VERSION 5.7 ;
  NOWIREEXTENSIONATPIN ON ;
  DIVIDERCHAR "/" ;
  BUSBITCHARS "[]" ;
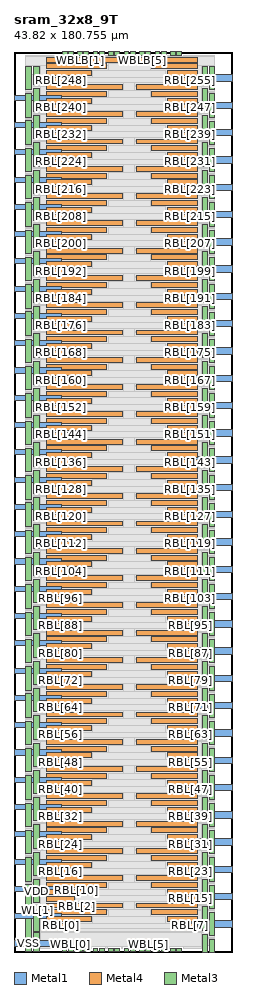
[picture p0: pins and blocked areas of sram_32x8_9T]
MACRO sram_32x8_9T
  CLASS BLOCK ;
  FOREIGN sram_32x8_9T ;
  ORIGIN -3.555 -0.080 ;
  SIZE 43.820 BY 180.755 ;
  PIN A[0]
    ANTENNADIFFAREA 2.832000 ;
    PORT
      LAYER Metal1 ;
        RECT 39.145 5.050 47.375 6.350 ;
    END
  END A[0]
  PIN A[1]
    ANTENNADIFFAREA 2.832000 ;
    PORT
      LAYER Metal1 ;
        RECT 39.145 10.530 47.375 11.830 ;
    END
  END A[1]
  PIN A[2]
    ANTENNADIFFAREA 2.832000 ;
    PORT
      LAYER Metal1 ;
        RECT 39.145 16.010 47.375 17.310 ;
    END
  END A[2]
  PIN A[3]
    ANTENNADIFFAREA 2.832000 ;
    PORT
      LAYER Metal1 ;
        RECT 39.145 21.490 47.375 22.790 ;
    END
  END A[3]
  PIN A[4]
    ANTENNADIFFAREA 2.832000 ;
    PORT
      LAYER Metal1 ;
        RECT 39.145 26.970 47.375 28.270 ;
    END
  END A[4]
  PIN A[5]
    ANTENNADIFFAREA 2.832000 ;
    PORT
      LAYER Metal1 ;
        RECT 39.145 32.450 47.375 33.750 ;
    END
  END A[5]
  PIN A[6]
    ANTENNADIFFAREA 2.832000 ;
    PORT
      LAYER Metal1 ;
        RECT 39.145 37.930 47.375 39.230 ;
    END
  END A[6]
  PIN A[7]
    ANTENNADIFFAREA 2.832000 ;
    PORT
      LAYER Metal1 ;
        RECT 39.145 43.410 47.375 44.710 ;
    END
  END A[7]
  PIN A[8]
    ANTENNADIFFAREA 2.832000 ;
    PORT
      LAYER Metal1 ;
        RECT 39.145 48.890 47.375 50.190 ;
    END
  END A[8]
  PIN A[9]
    ANTENNADIFFAREA 2.832000 ;
    PORT
      LAYER Metal1 ;
        RECT 39.145 54.370 47.375 55.670 ;
    END
  END A[9]
  PIN A[10]
    ANTENNADIFFAREA 2.832000 ;
    PORT
      LAYER Metal1 ;
        RECT 39.145 59.850 47.375 61.150 ;
    END
  END A[10]
  PIN A[11]
    ANTENNADIFFAREA 2.832000 ;
    PORT
      LAYER Metal1 ;
        RECT 39.145 65.330 47.375 66.630 ;
    END
  END A[11]
  PIN A[12]
    ANTENNADIFFAREA 2.832000 ;
    PORT
      LAYER Metal1 ;
        RECT 39.145 70.810 47.375 72.110 ;
    END
  END A[12]
  PIN A[13]
    ANTENNADIFFAREA 2.832000 ;
    PORT
      LAYER Metal1 ;
        RECT 39.145 76.290 47.375 77.590 ;
    END
  END A[13]
  PIN A[14]
    ANTENNADIFFAREA 2.832000 ;
    PORT
      LAYER Metal1 ;
        RECT 39.145 81.770 47.375 83.070 ;
    END
  END A[14]
  PIN A[15]
    ANTENNADIFFAREA 2.832000 ;
    PORT
      LAYER Metal1 ;
        RECT 39.145 87.250 47.375 88.550 ;
    END
  END A[15]
  PIN A[16]
    ANTENNADIFFAREA 2.832000 ;
    PORT
      LAYER Metal1 ;
        RECT 39.145 92.730 47.375 94.030 ;
    END
  END A[16]
  PIN A[17]
    ANTENNADIFFAREA 2.832000 ;
    PORT
      LAYER Metal1 ;
        RECT 39.145 98.210 47.375 99.510 ;
    END
  END A[17]
  PIN A[18]
    ANTENNADIFFAREA 2.832000 ;
    PORT
      LAYER Metal1 ;
        RECT 39.145 103.690 47.375 104.990 ;
    END
  END A[18]
  PIN A[19]
    ANTENNADIFFAREA 2.832000 ;
    PORT
      LAYER Metal1 ;
        RECT 39.145 109.170 47.375 110.470 ;
    END
  END A[19]
  PIN A[20]
    ANTENNADIFFAREA 2.832000 ;
    PORT
      LAYER Metal1 ;
        RECT 39.145 114.650 47.375 115.950 ;
    END
  END A[20]
  PIN A[21]
    ANTENNADIFFAREA 2.832000 ;
    PORT
      LAYER Metal1 ;
        RECT 39.145 120.130 47.375 121.430 ;
    END
  END A[21]
  PIN A[22]
    ANTENNADIFFAREA 2.832000 ;
    PORT
      LAYER Metal1 ;
        RECT 39.145 125.610 47.375 126.910 ;
    END
  END A[22]
  PIN A[23]
    ANTENNADIFFAREA 2.832000 ;
    PORT
      LAYER Metal1 ;
        RECT 39.145 131.090 47.375 132.390 ;
    END
  END A[23]
  PIN A[24]
    ANTENNADIFFAREA 2.832000 ;
    PORT
      LAYER Metal1 ;
        RECT 39.145 136.570 47.375 137.870 ;
    END
  END A[24]
  PIN A[25]
    ANTENNADIFFAREA 2.832000 ;
    PORT
      LAYER Metal1 ;
        RECT 39.145 142.050 47.375 143.350 ;
    END
  END A[25]
  PIN A[26]
    ANTENNADIFFAREA 2.832000 ;
    PORT
      LAYER Metal1 ;
        RECT 39.145 147.530 47.375 148.830 ;
    END
  END A[26]
  PIN A[27]
    ANTENNADIFFAREA 2.832000 ;
    PORT
      LAYER Metal1 ;
        RECT 39.145 153.010 47.375 154.310 ;
    END
  END A[27]
  PIN A[28]
    ANTENNADIFFAREA 2.832000 ;
    PORT
      LAYER Metal1 ;
        RECT 39.145 158.490 47.375 159.790 ;
    END
  END A[28]
  PIN A[29]
    ANTENNADIFFAREA 2.832000 ;
    PORT
      LAYER Metal1 ;
        RECT 39.145 163.970 47.375 165.270 ;
    END
  END A[29]
  PIN A[30]
    ANTENNADIFFAREA 2.832000 ;
    PORT
      LAYER Metal1 ;
        RECT 39.145 169.450 47.375 170.750 ;
    END
  END A[30]
  PIN A[31]
    ANTENNADIFFAREA 2.832000 ;
    PORT
      LAYER Metal1 ;
        RECT 39.145 174.930 47.375 176.230 ;
    END
  END A[31]
  PIN RBL[0]
    ANTENNADIFFAREA 0.511400 ;
    PORT
      LAYER Metal4 ;
        RECT 10.165 4.810 15.685 5.810 ;
    END
  END RBL[0]
  PIN RBL[1]
    ANTENNADIFFAREA 0.511400 ;
    PORT
      LAYER Metal4 ;
        RECT 10.165 6.180 19.075 7.180 ;
    END
  END RBL[1]
  PIN RBL[2]
    ANTENNADIFFAREA 0.511400 ;
    PORT
      LAYER Metal4 ;
        RECT 10.165 7.550 22.185 8.550 ;
    END
  END RBL[2]
  PIN RBL[3]
    ANTENNADIFFAREA 0.511400 ;
    PORT
      LAYER Metal4 ;
        RECT 10.165 8.920 25.295 9.920 ;
    END
  END RBL[3]
  PIN RBL[4]
    ANTENNADIFFAREA 0.511400 ;
    PORT
      LAYER Metal4 ;
        RECT 28.125 8.920 40.500 9.920 ;
    END
  END RBL[4]
  PIN RBL[5]
    ANTENNADIFFAREA 0.511400 ;
    PORT
      LAYER Metal4 ;
        RECT 31.235 7.550 40.500 8.550 ;
    END
  END RBL[5]
  PIN RBL[6]
    ANTENNADIFFAREA 0.511400 ;
    PORT
      LAYER Metal4 ;
        RECT 34.345 6.180 40.500 7.180 ;
    END
  END RBL[6]
  PIN RBL[7]
    ANTENNADIFFAREA 0.511400 ;
    PORT
      LAYER Metal4 ;
        RECT 37.455 4.810 40.500 5.810 ;
    END
  END RBL[7]
  PIN RBL[8]
    ANTENNADIFFAREA 0.511400 ;
    PORT
      LAYER Metal4 ;
        RECT 10.165 10.290 15.685 11.290 ;
    END
  END RBL[8]
  PIN RBL[9]
    ANTENNADIFFAREA 0.511400 ;
    PORT
      LAYER Metal4 ;
        RECT 10.165 11.660 19.075 12.660 ;
    END
  END RBL[9]
  PIN RBL[10]
    ANTENNADIFFAREA 0.511400 ;
    PORT
      LAYER Metal4 ;
        RECT 10.165 13.030 22.185 14.030 ;
    END
  END RBL[10]
  PIN RBL[11]
    ANTENNADIFFAREA 0.511400 ;
    PORT
      LAYER Metal4 ;
        RECT 10.165 14.400 25.295 15.400 ;
    END
  END RBL[11]
  PIN RBL[12]
    ANTENNADIFFAREA 0.511400 ;
    PORT
      LAYER Metal4 ;
        RECT 28.125 14.400 40.500 15.400 ;
    END
  END RBL[12]
  PIN RBL[13]
    ANTENNADIFFAREA 0.511400 ;
    PORT
      LAYER Metal4 ;
        RECT 31.235 13.030 40.500 14.030 ;
    END
  END RBL[13]
  PIN RBL[14]
    ANTENNADIFFAREA 0.511400 ;
    PORT
      LAYER Metal4 ;
        RECT 34.345 11.660 40.500 12.660 ;
    END
  END RBL[14]
  PIN RBL[15]
    ANTENNADIFFAREA 0.511400 ;
    PORT
      LAYER Metal4 ;
        RECT 37.455 10.290 40.500 11.290 ;
    END
  END RBL[15]
  PIN RBL[16]
    ANTENNADIFFAREA 0.511400 ;
    PORT
      LAYER Metal4 ;
        RECT 10.165 15.770 15.685 16.770 ;
    END
  END RBL[16]
  PIN RBL[17]
    ANTENNADIFFAREA 0.511400 ;
    PORT
      LAYER Metal4 ;
        RECT 10.165 17.140 19.075 18.140 ;
    END
  END RBL[17]
  PIN RBL[18]
    ANTENNADIFFAREA 0.511400 ;
    PORT
      LAYER Metal4 ;
        RECT 10.165 18.510 22.185 19.510 ;
    END
  END RBL[18]
  PIN RBL[19]
    ANTENNADIFFAREA 0.511400 ;
    PORT
      LAYER Metal4 ;
        RECT 10.165 19.880 25.295 20.880 ;
    END
  END RBL[19]
  PIN RBL[20]
    ANTENNADIFFAREA 0.511400 ;
    PORT
      LAYER Metal4 ;
        RECT 28.125 19.880 40.500 20.880 ;
    END
  END RBL[20]
  PIN RBL[21]
    ANTENNADIFFAREA 0.511400 ;
    PORT
      LAYER Metal4 ;
        RECT 31.235 18.510 40.500 19.510 ;
    END
  END RBL[21]
  PIN RBL[22]
    ANTENNADIFFAREA 0.511400 ;
    PORT
      LAYER Metal4 ;
        RECT 34.345 17.140 40.500 18.140 ;
    END
  END RBL[22]
  PIN RBL[23]
    ANTENNADIFFAREA 0.511400 ;
    PORT
      LAYER Metal4 ;
        RECT 37.455 15.770 40.500 16.770 ;
    END
  END RBL[23]
  PIN RBL[24]
    ANTENNADIFFAREA 0.511400 ;
    PORT
      LAYER Metal4 ;
        RECT 10.165 21.250 15.685 22.250 ;
    END
  END RBL[24]
  PIN RBL[25]
    ANTENNADIFFAREA 0.511400 ;
    PORT
      LAYER Metal4 ;
        RECT 10.165 22.620 19.075 23.620 ;
    END
  END RBL[25]
  PIN RBL[26]
    ANTENNADIFFAREA 0.511400 ;
    PORT
      LAYER Metal4 ;
        RECT 10.165 23.990 22.185 24.990 ;
    END
  END RBL[26]
  PIN RBL[27]
    ANTENNADIFFAREA 0.511400 ;
    PORT
      LAYER Metal4 ;
        RECT 10.165 25.360 25.295 26.360 ;
    END
  END RBL[27]
  PIN RBL[28]
    ANTENNADIFFAREA 0.511400 ;
    PORT
      LAYER Metal4 ;
        RECT 28.125 25.360 40.500 26.360 ;
    END
  END RBL[28]
  PIN RBL[29]
    ANTENNADIFFAREA 0.511400 ;
    PORT
      LAYER Metal4 ;
        RECT 31.235 23.990 40.500 24.990 ;
    END
  END RBL[29]
  PIN RBL[30]
    ANTENNADIFFAREA 0.511400 ;
    PORT
      LAYER Metal4 ;
        RECT 34.345 22.620 40.500 23.620 ;
    END
  END RBL[30]
  PIN RBL[31]
    ANTENNADIFFAREA 0.511400 ;
    PORT
      LAYER Metal4 ;
        RECT 37.455 21.250 40.500 22.250 ;
    END
  END RBL[31]
  PIN RBL[32]
    ANTENNADIFFAREA 0.511400 ;
    PORT
      LAYER Metal4 ;
        RECT 10.165 26.730 15.685 27.730 ;
    END
  END RBL[32]
  PIN RBL[33]
    ANTENNADIFFAREA 0.511400 ;
    PORT
      LAYER Metal4 ;
        RECT 10.165 28.100 19.075 29.100 ;
    END
  END RBL[33]
  PIN RBL[34]
    ANTENNADIFFAREA 0.511400 ;
    PORT
      LAYER Metal4 ;
        RECT 10.165 29.470 22.185 30.470 ;
    END
  END RBL[34]
  PIN RBL[35]
    ANTENNADIFFAREA 0.511400 ;
    PORT
      LAYER Metal4 ;
        RECT 10.165 30.840 25.295 31.840 ;
    END
  END RBL[35]
  PIN RBL[36]
    ANTENNADIFFAREA 0.511400 ;
    PORT
      LAYER Metal4 ;
        RECT 28.125 30.840 40.500 31.840 ;
    END
  END RBL[36]
  PIN RBL[37]
    ANTENNADIFFAREA 0.511400 ;
    PORT
      LAYER Metal4 ;
        RECT 31.235 29.470 40.500 30.470 ;
    END
  END RBL[37]
  PIN RBL[38]
    ANTENNADIFFAREA 0.511400 ;
    PORT
      LAYER Metal4 ;
        RECT 34.345 28.100 40.500 29.100 ;
    END
  END RBL[38]
  PIN RBL[39]
    ANTENNADIFFAREA 0.511400 ;
    PORT
      LAYER Metal4 ;
        RECT 37.455 26.730 40.500 27.730 ;
    END
  END RBL[39]
  PIN RBL[40]
    ANTENNADIFFAREA 0.511400 ;
    PORT
      LAYER Metal4 ;
        RECT 10.165 32.210 15.685 33.210 ;
    END
  END RBL[40]
  PIN RBL[41]
    ANTENNADIFFAREA 0.511400 ;
    PORT
      LAYER Metal4 ;
        RECT 10.165 33.580 19.075 34.580 ;
    END
  END RBL[41]
  PIN RBL[42]
    ANTENNADIFFAREA 0.511400 ;
    PORT
      LAYER Metal4 ;
        RECT 10.165 34.950 22.185 35.950 ;
    END
  END RBL[42]
  PIN RBL[43]
    ANTENNADIFFAREA 0.511400 ;
    PORT
      LAYER Metal4 ;
        RECT 10.165 36.320 25.295 37.320 ;
    END
  END RBL[43]
  PIN RBL[44]
    ANTENNADIFFAREA 0.511400 ;
    PORT
      LAYER Metal4 ;
        RECT 28.125 36.320 40.500 37.320 ;
    END
  END RBL[44]
  PIN RBL[45]
    ANTENNADIFFAREA 0.511400 ;
    PORT
      LAYER Metal4 ;
        RECT 31.235 34.950 40.500 35.950 ;
    END
  END RBL[45]
  PIN RBL[46]
    ANTENNADIFFAREA 0.511400 ;
    PORT
      LAYER Metal4 ;
        RECT 34.345 33.580 40.500 34.580 ;
    END
  END RBL[46]
  PIN RBL[47]
    ANTENNADIFFAREA 0.511400 ;
    PORT
      LAYER Metal4 ;
        RECT 37.455 32.210 40.500 33.210 ;
    END
  END RBL[47]
  PIN RBL[48]
    ANTENNADIFFAREA 0.511400 ;
    PORT
      LAYER Metal4 ;
        RECT 10.165 37.690 15.685 38.690 ;
    END
  END RBL[48]
  PIN RBL[49]
    ANTENNADIFFAREA 0.511400 ;
    PORT
      LAYER Metal4 ;
        RECT 10.165 39.060 19.075 40.060 ;
    END
  END RBL[49]
  PIN RBL[50]
    ANTENNADIFFAREA 0.511400 ;
    PORT
      LAYER Metal4 ;
        RECT 10.165 40.430 22.185 41.430 ;
    END
  END RBL[50]
  PIN RBL[51]
    ANTENNADIFFAREA 0.511400 ;
    PORT
      LAYER Metal4 ;
        RECT 10.165 41.800 25.295 42.800 ;
    END
  END RBL[51]
  PIN RBL[52]
    ANTENNADIFFAREA 0.511400 ;
    PORT
      LAYER Metal4 ;
        RECT 28.125 41.800 40.500 42.800 ;
    END
  END RBL[52]
  PIN RBL[53]
    ANTENNADIFFAREA 0.511400 ;
    PORT
      LAYER Metal4 ;
        RECT 31.235 40.430 40.500 41.430 ;
    END
  END RBL[53]
  PIN RBL[54]
    ANTENNADIFFAREA 0.511400 ;
    PORT
      LAYER Metal4 ;
        RECT 34.345 39.060 40.500 40.060 ;
    END
  END RBL[54]
  PIN RBL[55]
    ANTENNADIFFAREA 0.511400 ;
    PORT
      LAYER Metal4 ;
        RECT 37.455 37.690 40.500 38.690 ;
    END
  END RBL[55]
  PIN RBL[56]
    ANTENNADIFFAREA 0.511400 ;
    PORT
      LAYER Metal4 ;
        RECT 10.165 43.170 15.685 44.170 ;
    END
  END RBL[56]
  PIN RBL[57]
    ANTENNADIFFAREA 0.511400 ;
    PORT
      LAYER Metal4 ;
        RECT 10.165 44.540 19.075 45.540 ;
    END
  END RBL[57]
  PIN RBL[58]
    ANTENNADIFFAREA 0.511400 ;
    PORT
      LAYER Metal4 ;
        RECT 10.165 45.910 22.185 46.910 ;
    END
  END RBL[58]
  PIN RBL[59]
    ANTENNADIFFAREA 0.511400 ;
    PORT
      LAYER Metal4 ;
        RECT 10.165 47.280 25.295 48.280 ;
    END
  END RBL[59]
  PIN RBL[60]
    ANTENNADIFFAREA 0.511400 ;
    PORT
      LAYER Metal4 ;
        RECT 28.125 47.280 40.500 48.280 ;
    END
  END RBL[60]
  PIN RBL[61]
    ANTENNADIFFAREA 0.511400 ;
    PORT
      LAYER Metal4 ;
        RECT 31.235 45.910 40.500 46.910 ;
    END
  END RBL[61]
  PIN RBL[62]
    ANTENNADIFFAREA 0.511400 ;
    PORT
      LAYER Metal4 ;
        RECT 34.345 44.540 40.500 45.540 ;
    END
  END RBL[62]
  PIN RBL[63]
    ANTENNADIFFAREA 0.511400 ;
    PORT
      LAYER Metal4 ;
        RECT 37.455 43.170 40.500 44.170 ;
    END
  END RBL[63]
  PIN RBL[64]
    ANTENNADIFFAREA 0.511400 ;
    PORT
      LAYER Metal4 ;
        RECT 10.165 48.650 15.685 49.650 ;
    END
  END RBL[64]
  PIN RBL[65]
    ANTENNADIFFAREA 0.511400 ;
    PORT
      LAYER Metal4 ;
        RECT 10.165 50.020 19.075 51.020 ;
    END
  END RBL[65]
  PIN RBL[66]
    ANTENNADIFFAREA 0.511400 ;
    PORT
      LAYER Metal4 ;
        RECT 10.165 51.390 22.185 52.390 ;
    END
  END RBL[66]
  PIN RBL[67]
    ANTENNADIFFAREA 0.511400 ;
    PORT
      LAYER Metal4 ;
        RECT 10.165 52.760 25.295 53.760 ;
    END
  END RBL[67]
  PIN RBL[68]
    ANTENNADIFFAREA 0.511400 ;
    PORT
      LAYER Metal4 ;
        RECT 28.125 52.760 40.500 53.760 ;
    END
  END RBL[68]
  PIN RBL[69]
    ANTENNADIFFAREA 0.511400 ;
    PORT
      LAYER Metal4 ;
        RECT 31.235 51.390 40.500 52.390 ;
    END
  END RBL[69]
  PIN RBL[70]
    ANTENNADIFFAREA 0.511400 ;
    PORT
      LAYER Metal4 ;
        RECT 34.345 50.020 40.500 51.020 ;
    END
  END RBL[70]
  PIN RBL[71]
    ANTENNADIFFAREA 0.511400 ;
    PORT
      LAYER Metal4 ;
        RECT 37.455 48.650 40.500 49.650 ;
    END
  END RBL[71]
  PIN RBL[72]
    ANTENNADIFFAREA 0.511400 ;
    PORT
      LAYER Metal4 ;
        RECT 10.165 54.130 15.685 55.130 ;
    END
  END RBL[72]
  PIN RBL[73]
    ANTENNADIFFAREA 0.511400 ;
    PORT
      LAYER Metal4 ;
        RECT 10.165 55.500 19.075 56.500 ;
    END
  END RBL[73]
  PIN RBL[74]
    ANTENNADIFFAREA 0.511400 ;
    PORT
      LAYER Metal4 ;
        RECT 10.165 56.870 22.185 57.870 ;
    END
  END RBL[74]
  PIN RBL[75]
    ANTENNADIFFAREA 0.511400 ;
    PORT
      LAYER Metal4 ;
        RECT 10.165 58.240 25.295 59.240 ;
    END
  END RBL[75]
  PIN RBL[76]
    ANTENNADIFFAREA 0.511400 ;
    PORT
      LAYER Metal4 ;
        RECT 28.125 58.240 40.500 59.240 ;
    END
  END RBL[76]
  PIN RBL[77]
    ANTENNADIFFAREA 0.511400 ;
    PORT
      LAYER Metal4 ;
        RECT 31.235 56.870 40.500 57.870 ;
    END
  END RBL[77]
  PIN RBL[78]
    ANTENNADIFFAREA 0.511400 ;
    PORT
      LAYER Metal4 ;
        RECT 34.345 55.500 40.500 56.500 ;
    END
  END RBL[78]
  PIN RBL[79]
    ANTENNADIFFAREA 0.511400 ;
    PORT
      LAYER Metal4 ;
        RECT 37.455 54.130 40.500 55.130 ;
    END
  END RBL[79]
  PIN RBL[80]
    ANTENNADIFFAREA 0.511400 ;
    PORT
      LAYER Metal4 ;
        RECT 10.165 59.610 15.685 60.610 ;
    END
  END RBL[80]
  PIN RBL[81]
    ANTENNADIFFAREA 0.511400 ;
    PORT
      LAYER Metal4 ;
        RECT 10.165 60.980 19.075 61.980 ;
    END
  END RBL[81]
  PIN RBL[82]
    ANTENNADIFFAREA 0.511400 ;
    PORT
      LAYER Metal4 ;
        RECT 10.165 62.350 22.185 63.350 ;
    END
  END RBL[82]
  PIN RBL[83]
    ANTENNADIFFAREA 0.511400 ;
    PORT
      LAYER Metal4 ;
        RECT 10.165 63.720 25.295 64.720 ;
    END
  END RBL[83]
  PIN RBL[84]
    ANTENNADIFFAREA 0.511400 ;
    PORT
      LAYER Metal4 ;
        RECT 28.125 63.720 40.500 64.720 ;
    END
  END RBL[84]
  PIN RBL[85]
    ANTENNADIFFAREA 0.511400 ;
    PORT
      LAYER Metal4 ;
        RECT 31.235 62.350 40.500 63.350 ;
    END
  END RBL[85]
  PIN RBL[86]
    ANTENNADIFFAREA 0.511400 ;
    PORT
      LAYER Metal4 ;
        RECT 34.345 60.980 40.500 61.980 ;
    END
  END RBL[86]
  PIN RBL[87]
    ANTENNADIFFAREA 0.511400 ;
    PORT
      LAYER Metal4 ;
        RECT 37.455 59.610 40.500 60.610 ;
    END
  END RBL[87]
  PIN RBL[88]
    ANTENNADIFFAREA 0.511400 ;
    PORT
      LAYER Metal4 ;
        RECT 10.165 65.090 15.685 66.090 ;
    END
  END RBL[88]
  PIN RBL[89]
    ANTENNADIFFAREA 0.511400 ;
    PORT
      LAYER Metal4 ;
        RECT 10.165 66.460 19.075 67.460 ;
    END
  END RBL[89]
  PIN RBL[90]
    ANTENNADIFFAREA 0.511400 ;
    PORT
      LAYER Metal4 ;
        RECT 10.165 67.830 22.185 68.830 ;
    END
  END RBL[90]
  PIN RBL[91]
    ANTENNADIFFAREA 0.511400 ;
    PORT
      LAYER Metal4 ;
        RECT 10.165 69.200 25.295 70.200 ;
    END
  END RBL[91]
  PIN RBL[92]
    ANTENNADIFFAREA 0.511400 ;
    PORT
      LAYER Metal4 ;
        RECT 28.125 69.200 40.500 70.200 ;
    END
  END RBL[92]
  PIN RBL[93]
    ANTENNADIFFAREA 0.511400 ;
    PORT
      LAYER Metal4 ;
        RECT 31.235 67.830 40.500 68.830 ;
    END
  END RBL[93]
  PIN RBL[94]
    ANTENNADIFFAREA 0.511400 ;
    PORT
      LAYER Metal4 ;
        RECT 34.345 66.460 40.500 67.460 ;
    END
  END RBL[94]
  PIN RBL[95]
    ANTENNADIFFAREA 0.511400 ;
    PORT
      LAYER Metal4 ;
        RECT 37.455 65.090 40.500 66.090 ;
    END
  END RBL[95]
  PIN RBL[96]
    ANTENNADIFFAREA 0.511400 ;
    PORT
      LAYER Metal4 ;
        RECT 10.165 70.570 15.685 71.570 ;
    END
  END RBL[96]
  PIN RBL[97]
    ANTENNADIFFAREA 0.511400 ;
    PORT
      LAYER Metal4 ;
        RECT 10.165 71.940 19.075 72.940 ;
    END
  END RBL[97]
  PIN RBL[98]
    ANTENNADIFFAREA 0.511400 ;
    PORT
      LAYER Metal4 ;
        RECT 10.165 73.310 22.185 74.310 ;
    END
  END RBL[98]
  PIN RBL[99]
    ANTENNADIFFAREA 0.511400 ;
    PORT
      LAYER Metal4 ;
        RECT 10.165 74.680 25.295 75.680 ;
    END
  END RBL[99]
  PIN RBL[100]
    ANTENNADIFFAREA 0.511400 ;
    PORT
      LAYER Metal4 ;
        RECT 28.125 74.680 40.500 75.680 ;
    END
  END RBL[100]
  PIN RBL[101]
    ANTENNADIFFAREA 0.511400 ;
    PORT
      LAYER Metal4 ;
        RECT 31.235 73.310 40.500 74.310 ;
    END
  END RBL[101]
  PIN RBL[102]
    ANTENNADIFFAREA 0.511400 ;
    PORT
      LAYER Metal4 ;
        RECT 34.345 71.940 40.500 72.940 ;
    END
  END RBL[102]
  PIN RBL[103]
    ANTENNADIFFAREA 0.511400 ;
    PORT
      LAYER Metal4 ;
        RECT 37.455 70.570 40.500 71.570 ;
    END
  END RBL[103]
  PIN RBL[104]
    ANTENNADIFFAREA 0.511400 ;
    PORT
      LAYER Metal4 ;
        RECT 10.165 76.050 15.685 77.050 ;
    END
  END RBL[104]
  PIN RBL[105]
    ANTENNADIFFAREA 0.511400 ;
    PORT
      LAYER Metal4 ;
        RECT 10.165 77.420 19.075 78.420 ;
    END
  END RBL[105]
  PIN RBL[106]
    ANTENNADIFFAREA 0.511400 ;
    PORT
      LAYER Metal4 ;
        RECT 10.165 78.790 22.185 79.790 ;
    END
  END RBL[106]
  PIN RBL[107]
    ANTENNADIFFAREA 0.511400 ;
    PORT
      LAYER Metal4 ;
        RECT 10.165 80.160 25.295 81.160 ;
    END
  END RBL[107]
  PIN RBL[108]
    ANTENNADIFFAREA 0.511400 ;
    PORT
      LAYER Metal4 ;
        RECT 28.125 80.160 40.500 81.160 ;
    END
  END RBL[108]
  PIN RBL[109]
    ANTENNADIFFAREA 0.511400 ;
    PORT
      LAYER Metal4 ;
        RECT 31.235 78.790 40.500 79.790 ;
    END
  END RBL[109]
  PIN RBL[110]
    ANTENNADIFFAREA 0.511400 ;
    PORT
      LAYER Metal4 ;
        RECT 34.345 77.420 40.500 78.420 ;
    END
  END RBL[110]
  PIN RBL[111]
    ANTENNADIFFAREA 0.511400 ;
    PORT
      LAYER Metal4 ;
        RECT 37.455 76.050 40.500 77.050 ;
    END
  END RBL[111]
  PIN RBL[112]
    ANTENNADIFFAREA 0.511400 ;
    PORT
      LAYER Metal4 ;
        RECT 10.165 81.530 15.685 82.530 ;
    END
  END RBL[112]
  PIN RBL[113]
    ANTENNADIFFAREA 0.511400 ;
    PORT
      LAYER Metal4 ;
        RECT 10.165 82.900 19.075 83.900 ;
    END
  END RBL[113]
  PIN RBL[114]
    ANTENNADIFFAREA 0.511400 ;
    PORT
      LAYER Metal4 ;
        RECT 10.165 84.270 22.185 85.270 ;
    END
  END RBL[114]
  PIN RBL[115]
    ANTENNADIFFAREA 0.511400 ;
    PORT
      LAYER Metal4 ;
        RECT 10.165 85.640 25.295 86.640 ;
    END
  END RBL[115]
  PIN RBL[116]
    ANTENNADIFFAREA 0.511400 ;
    PORT
      LAYER Metal4 ;
        RECT 28.125 85.640 40.500 86.640 ;
    END
  END RBL[116]
  PIN RBL[117]
    ANTENNADIFFAREA 0.511400 ;
    PORT
      LAYER Metal4 ;
        RECT 31.235 84.270 40.500 85.270 ;
    END
  END RBL[117]
  PIN RBL[118]
    ANTENNADIFFAREA 0.511400 ;
    PORT
      LAYER Metal4 ;
        RECT 34.345 82.900 40.500 83.900 ;
    END
  END RBL[118]
  PIN RBL[119]
    ANTENNADIFFAREA 0.511400 ;
    PORT
      LAYER Metal4 ;
        RECT 37.455 81.530 40.500 82.530 ;
    END
  END RBL[119]
  PIN RBL[120]
    ANTENNADIFFAREA 0.511400 ;
    PORT
      LAYER Metal4 ;
        RECT 10.165 87.010 15.685 88.010 ;
    END
  END RBL[120]
  PIN RBL[121]
    ANTENNADIFFAREA 0.511400 ;
    PORT
      LAYER Metal4 ;
        RECT 10.165 88.380 19.075 89.380 ;
    END
  END RBL[121]
  PIN RBL[122]
    ANTENNADIFFAREA 0.511400 ;
    PORT
      LAYER Metal4 ;
        RECT 10.165 89.750 22.185 90.750 ;
    END
  END RBL[122]
  PIN RBL[123]
    ANTENNADIFFAREA 0.511400 ;
    PORT
      LAYER Metal4 ;
        RECT 10.165 91.120 25.295 92.120 ;
    END
  END RBL[123]
  PIN RBL[124]
    ANTENNADIFFAREA 0.511400 ;
    PORT
      LAYER Metal4 ;
        RECT 28.125 91.120 40.500 92.120 ;
    END
  END RBL[124]
  PIN RBL[125]
    ANTENNADIFFAREA 0.511400 ;
    PORT
      LAYER Metal4 ;
        RECT 31.235 89.750 40.500 90.750 ;
    END
  END RBL[125]
  PIN RBL[126]
    ANTENNADIFFAREA 0.511400 ;
    PORT
      LAYER Metal4 ;
        RECT 34.345 88.380 40.500 89.380 ;
    END
  END RBL[126]
  PIN RBL[127]
    ANTENNADIFFAREA 0.511400 ;
    PORT
      LAYER Metal4 ;
        RECT 37.455 87.010 40.500 88.010 ;
    END
  END RBL[127]
  PIN RBL[128]
    ANTENNADIFFAREA 0.511400 ;
    PORT
      LAYER Metal4 ;
        RECT 10.165 92.490 15.685 93.490 ;
    END
  END RBL[128]
  PIN RBL[129]
    ANTENNADIFFAREA 0.511400 ;
    PORT
      LAYER Metal4 ;
        RECT 10.165 93.860 19.075 94.860 ;
    END
  END RBL[129]
  PIN RBL[130]
    ANTENNADIFFAREA 0.511400 ;
    PORT
      LAYER Metal4 ;
        RECT 10.165 95.230 22.185 96.230 ;
    END
  END RBL[130]
  PIN RBL[131]
    ANTENNADIFFAREA 0.511400 ;
    PORT
      LAYER Metal4 ;
        RECT 10.165 96.600 25.295 97.600 ;
    END
  END RBL[131]
  PIN RBL[132]
    ANTENNADIFFAREA 0.511400 ;
    PORT
      LAYER Metal4 ;
        RECT 28.125 96.600 40.500 97.600 ;
    END
  END RBL[132]
  PIN RBL[133]
    ANTENNADIFFAREA 0.511400 ;
    PORT
      LAYER Metal4 ;
        RECT 31.235 95.230 40.500 96.230 ;
    END
  END RBL[133]
  PIN RBL[134]
    ANTENNADIFFAREA 0.511400 ;
    PORT
      LAYER Metal4 ;
        RECT 34.345 93.860 40.500 94.860 ;
    END
  END RBL[134]
  PIN RBL[135]
    ANTENNADIFFAREA 0.511400 ;
    PORT
      LAYER Metal4 ;
        RECT 37.455 92.490 40.500 93.490 ;
    END
  END RBL[135]
  PIN RBL[136]
    ANTENNADIFFAREA 0.511400 ;
    PORT
      LAYER Metal4 ;
        RECT 10.165 97.970 15.685 98.970 ;
    END
  END RBL[136]
  PIN RBL[137]
    ANTENNADIFFAREA 0.511400 ;
    PORT
      LAYER Metal4 ;
        RECT 10.165 99.340 19.075 100.340 ;
    END
  END RBL[137]
  PIN RBL[138]
    ANTENNADIFFAREA 0.511400 ;
    PORT
      LAYER Metal4 ;
        RECT 10.165 100.710 22.185 101.710 ;
    END
  END RBL[138]
  PIN RBL[139]
    ANTENNADIFFAREA 0.511400 ;
    PORT
      LAYER Metal4 ;
        RECT 10.165 102.080 25.295 103.080 ;
    END
  END RBL[139]
  PIN RBL[140]
    ANTENNADIFFAREA 0.511400 ;
    PORT
      LAYER Metal4 ;
        RECT 28.125 102.080 40.500 103.080 ;
    END
  END RBL[140]
  PIN RBL[141]
    ANTENNADIFFAREA 0.511400 ;
    PORT
      LAYER Metal4 ;
        RECT 31.235 100.710 40.500 101.710 ;
    END
  END RBL[141]
  PIN RBL[142]
    ANTENNADIFFAREA 0.511400 ;
    PORT
      LAYER Metal4 ;
        RECT 34.345 99.340 40.500 100.340 ;
    END
  END RBL[142]
  PIN RBL[143]
    ANTENNADIFFAREA 0.511400 ;
    PORT
      LAYER Metal4 ;
        RECT 37.455 97.970 40.500 98.970 ;
    END
  END RBL[143]
  PIN RBL[144]
    ANTENNADIFFAREA 0.511400 ;
    PORT
      LAYER Metal4 ;
        RECT 10.165 103.450 15.685 104.450 ;
    END
  END RBL[144]
  PIN RBL[145]
    ANTENNADIFFAREA 0.511400 ;
    PORT
      LAYER Metal4 ;
        RECT 10.165 104.820 19.075 105.820 ;
    END
  END RBL[145]
  PIN RBL[146]
    ANTENNADIFFAREA 0.511400 ;
    PORT
      LAYER Metal4 ;
        RECT 10.165 106.190 22.185 107.190 ;
    END
  END RBL[146]
  PIN RBL[147]
    ANTENNADIFFAREA 0.511400 ;
    PORT
      LAYER Metal4 ;
        RECT 10.165 107.560 25.295 108.560 ;
    END
  END RBL[147]
  PIN RBL[148]
    ANTENNADIFFAREA 0.511400 ;
    PORT
      LAYER Metal4 ;
        RECT 28.125 107.560 40.500 108.560 ;
    END
  END RBL[148]
  PIN RBL[149]
    ANTENNADIFFAREA 0.511400 ;
    PORT
      LAYER Metal4 ;
        RECT 31.235 106.190 40.500 107.190 ;
    END
  END RBL[149]
  PIN RBL[150]
    ANTENNADIFFAREA 0.511400 ;
    PORT
      LAYER Metal4 ;
        RECT 34.345 104.820 40.500 105.820 ;
    END
  END RBL[150]
  PIN RBL[151]
    ANTENNADIFFAREA 0.511400 ;
    PORT
      LAYER Metal4 ;
        RECT 37.455 103.450 40.500 104.450 ;
    END
  END RBL[151]
  PIN RBL[152]
    ANTENNADIFFAREA 0.511400 ;
    PORT
      LAYER Metal4 ;
        RECT 10.165 108.930 15.685 109.930 ;
    END
  END RBL[152]
  PIN RBL[153]
    ANTENNADIFFAREA 0.511400 ;
    PORT
      LAYER Metal4 ;
        RECT 10.165 110.300 19.075 111.300 ;
    END
  END RBL[153]
  PIN RBL[154]
    ANTENNADIFFAREA 0.511400 ;
    PORT
      LAYER Metal4 ;
        RECT 10.165 111.670 22.185 112.670 ;
    END
  END RBL[154]
  PIN RBL[155]
    ANTENNADIFFAREA 0.511400 ;
    PORT
      LAYER Metal4 ;
        RECT 10.165 113.040 25.295 114.040 ;
    END
  END RBL[155]
  PIN RBL[156]
    ANTENNADIFFAREA 0.511400 ;
    PORT
      LAYER Metal4 ;
        RECT 28.125 113.040 40.500 114.040 ;
    END
  END RBL[156]
  PIN RBL[157]
    ANTENNADIFFAREA 0.511400 ;
    PORT
      LAYER Metal4 ;
        RECT 31.235 111.670 40.500 112.670 ;
    END
  END RBL[157]
  PIN RBL[158]
    ANTENNADIFFAREA 0.511400 ;
    PORT
      LAYER Metal4 ;
        RECT 34.345 110.300 40.500 111.300 ;
    END
  END RBL[158]
  PIN RBL[159]
    ANTENNADIFFAREA 0.511400 ;
    PORT
      LAYER Metal4 ;
        RECT 37.455 108.930 40.500 109.930 ;
    END
  END RBL[159]
  PIN RBL[160]
    ANTENNADIFFAREA 0.511400 ;
    PORT
      LAYER Metal4 ;
        RECT 10.165 114.410 15.685 115.410 ;
    END
  END RBL[160]
  PIN RBL[161]
    ANTENNADIFFAREA 0.511400 ;
    PORT
      LAYER Metal4 ;
        RECT 10.165 115.780 19.075 116.780 ;
    END
  END RBL[161]
  PIN RBL[162]
    ANTENNADIFFAREA 0.511400 ;
    PORT
      LAYER Metal4 ;
        RECT 10.165 117.150 22.185 118.150 ;
    END
  END RBL[162]
  PIN RBL[163]
    ANTENNADIFFAREA 0.511400 ;
    PORT
      LAYER Metal4 ;
        RECT 10.165 118.520 25.295 119.520 ;
    END
  END RBL[163]
  PIN RBL[164]
    ANTENNADIFFAREA 0.511400 ;
    PORT
      LAYER Metal4 ;
        RECT 28.125 118.520 40.500 119.520 ;
    END
  END RBL[164]
  PIN RBL[165]
    ANTENNADIFFAREA 0.511400 ;
    PORT
      LAYER Metal4 ;
        RECT 31.235 117.150 40.500 118.150 ;
    END
  END RBL[165]
  PIN RBL[166]
    ANTENNADIFFAREA 0.511400 ;
    PORT
      LAYER Metal4 ;
        RECT 34.345 115.780 40.500 116.780 ;
    END
  END RBL[166]
  PIN RBL[167]
    ANTENNADIFFAREA 0.511400 ;
    PORT
      LAYER Metal4 ;
        RECT 37.455 114.410 40.500 115.410 ;
    END
  END RBL[167]
  PIN RBL[168]
    ANTENNADIFFAREA 0.511400 ;
    PORT
      LAYER Metal4 ;
        RECT 10.165 119.890 15.685 120.890 ;
    END
  END RBL[168]
  PIN RBL[169]
    ANTENNADIFFAREA 0.511400 ;
    PORT
      LAYER Metal4 ;
        RECT 10.165 121.260 19.075 122.260 ;
    END
  END RBL[169]
  PIN RBL[170]
    ANTENNADIFFAREA 0.511400 ;
    PORT
      LAYER Metal4 ;
        RECT 10.165 122.630 22.185 123.630 ;
    END
  END RBL[170]
  PIN RBL[171]
    ANTENNADIFFAREA 0.511400 ;
    PORT
      LAYER Metal4 ;
        RECT 10.165 124.000 25.295 125.000 ;
    END
  END RBL[171]
  PIN RBL[172]
    ANTENNADIFFAREA 0.511400 ;
    PORT
      LAYER Metal4 ;
        RECT 28.125 124.000 40.500 125.000 ;
    END
  END RBL[172]
  PIN RBL[173]
    ANTENNADIFFAREA 0.511400 ;
    PORT
      LAYER Metal4 ;
        RECT 31.235 122.630 40.500 123.630 ;
    END
  END RBL[173]
  PIN RBL[174]
    ANTENNADIFFAREA 0.511400 ;
    PORT
      LAYER Metal4 ;
        RECT 34.345 121.260 40.500 122.260 ;
    END
  END RBL[174]
  PIN RBL[175]
    ANTENNADIFFAREA 0.511400 ;
    PORT
      LAYER Metal4 ;
        RECT 37.455 119.890 40.500 120.890 ;
    END
  END RBL[175]
  PIN RBL[176]
    ANTENNADIFFAREA 0.511400 ;
    PORT
      LAYER Metal4 ;
        RECT 10.165 125.370 15.685 126.370 ;
    END
  END RBL[176]
  PIN RBL[177]
    ANTENNADIFFAREA 0.511400 ;
    PORT
      LAYER Metal4 ;
        RECT 10.165 126.740 19.075 127.740 ;
    END
  END RBL[177]
  PIN RBL[178]
    ANTENNADIFFAREA 0.511400 ;
    PORT
      LAYER Metal4 ;
        RECT 10.165 128.110 22.185 129.110 ;
    END
  END RBL[178]
  PIN RBL[179]
    ANTENNADIFFAREA 0.511400 ;
    PORT
      LAYER Metal4 ;
        RECT 10.165 129.480 25.295 130.480 ;
    END
  END RBL[179]
  PIN RBL[180]
    ANTENNADIFFAREA 0.511400 ;
    PORT
      LAYER Metal4 ;
        RECT 28.125 129.480 40.500 130.480 ;
    END
  END RBL[180]
  PIN RBL[181]
    ANTENNADIFFAREA 0.511400 ;
    PORT
      LAYER Metal4 ;
        RECT 31.235 128.110 40.500 129.110 ;
    END
  END RBL[181]
  PIN RBL[182]
    ANTENNADIFFAREA 0.511400 ;
    PORT
      LAYER Metal4 ;
        RECT 34.345 126.740 40.500 127.740 ;
    END
  END RBL[182]
  PIN RBL[183]
    ANTENNADIFFAREA 0.511400 ;
    PORT
      LAYER Metal4 ;
        RECT 37.455 125.370 40.500 126.370 ;
    END
  END RBL[183]
  PIN RBL[184]
    ANTENNADIFFAREA 0.511400 ;
    PORT
      LAYER Metal4 ;
        RECT 10.165 130.850 15.685 131.850 ;
    END
  END RBL[184]
  PIN RBL[185]
    ANTENNADIFFAREA 0.511400 ;
    PORT
      LAYER Metal4 ;
        RECT 10.165 132.220 19.075 133.220 ;
    END
  END RBL[185]
  PIN RBL[186]
    ANTENNADIFFAREA 0.511400 ;
    PORT
      LAYER Metal4 ;
        RECT 10.165 133.590 22.185 134.590 ;
    END
  END RBL[186]
  PIN RBL[187]
    ANTENNADIFFAREA 0.511400 ;
    PORT
      LAYER Metal4 ;
        RECT 10.165 134.960 25.295 135.960 ;
    END
  END RBL[187]
  PIN RBL[188]
    ANTENNADIFFAREA 0.511400 ;
    PORT
      LAYER Metal4 ;
        RECT 28.125 134.960 40.500 135.960 ;
    END
  END RBL[188]
  PIN RBL[189]
    ANTENNADIFFAREA 0.511400 ;
    PORT
      LAYER Metal4 ;
        RECT 31.235 133.590 40.500 134.590 ;
    END
  END RBL[189]
  PIN RBL[190]
    ANTENNADIFFAREA 0.511400 ;
    PORT
      LAYER Metal4 ;
        RECT 34.345 132.220 40.500 133.220 ;
    END
  END RBL[190]
  PIN RBL[191]
    ANTENNADIFFAREA 0.511400 ;
    PORT
      LAYER Metal4 ;
        RECT 37.455 130.850 40.500 131.850 ;
    END
  END RBL[191]
  PIN RBL[192]
    ANTENNADIFFAREA 0.511400 ;
    PORT
      LAYER Metal4 ;
        RECT 10.165 136.330 15.685 137.330 ;
    END
  END RBL[192]
  PIN RBL[193]
    ANTENNADIFFAREA 0.511400 ;
    PORT
      LAYER Metal4 ;
        RECT 10.165 137.700 19.075 138.700 ;
    END
  END RBL[193]
  PIN RBL[194]
    ANTENNADIFFAREA 0.511400 ;
    PORT
      LAYER Metal4 ;
        RECT 10.165 139.070 22.185 140.070 ;
    END
  END RBL[194]
  PIN RBL[195]
    ANTENNADIFFAREA 0.511400 ;
    PORT
      LAYER Metal4 ;
        RECT 10.165 140.440 25.295 141.440 ;
    END
  END RBL[195]
  PIN RBL[196]
    ANTENNADIFFAREA 0.511400 ;
    PORT
      LAYER Metal4 ;
        RECT 28.125 140.440 40.500 141.440 ;
    END
  END RBL[196]
  PIN RBL[197]
    ANTENNADIFFAREA 0.511400 ;
    PORT
      LAYER Metal4 ;
        RECT 31.235 139.070 40.500 140.070 ;
    END
  END RBL[197]
  PIN RBL[198]
    ANTENNADIFFAREA 0.511400 ;
    PORT
      LAYER Metal4 ;
        RECT 34.345 137.700 40.500 138.700 ;
    END
  END RBL[198]
  PIN RBL[199]
    ANTENNADIFFAREA 0.511400 ;
    PORT
      LAYER Metal4 ;
        RECT 37.455 136.330 40.500 137.330 ;
    END
  END RBL[199]
  PIN RBL[200]
    ANTENNADIFFAREA 0.511400 ;
    PORT
      LAYER Metal4 ;
        RECT 10.165 141.810 15.685 142.810 ;
    END
  END RBL[200]
  PIN RBL[201]
    ANTENNADIFFAREA 0.511400 ;
    PORT
      LAYER Metal4 ;
        RECT 10.165 143.180 19.075 144.180 ;
    END
  END RBL[201]
  PIN RBL[202]
    ANTENNADIFFAREA 0.511400 ;
    PORT
      LAYER Metal4 ;
        RECT 10.165 144.550 22.185 145.550 ;
    END
  END RBL[202]
  PIN RBL[203]
    ANTENNADIFFAREA 0.511400 ;
    PORT
      LAYER Metal4 ;
        RECT 10.165 145.920 25.295 146.920 ;
    END
  END RBL[203]
  PIN RBL[204]
    ANTENNADIFFAREA 0.511400 ;
    PORT
      LAYER Metal4 ;
        RECT 28.125 145.920 40.500 146.920 ;
    END
  END RBL[204]
  PIN RBL[205]
    ANTENNADIFFAREA 0.511400 ;
    PORT
      LAYER Metal4 ;
        RECT 31.235 144.550 40.500 145.550 ;
    END
  END RBL[205]
  PIN RBL[206]
    ANTENNADIFFAREA 0.511400 ;
    PORT
      LAYER Metal4 ;
        RECT 34.345 143.180 40.500 144.180 ;
    END
  END RBL[206]
  PIN RBL[207]
    ANTENNADIFFAREA 0.511400 ;
    PORT
      LAYER Metal4 ;
        RECT 37.455 141.810 40.500 142.810 ;
    END
  END RBL[207]
  PIN RBL[208]
    ANTENNADIFFAREA 0.511400 ;
    PORT
      LAYER Metal4 ;
        RECT 10.165 147.290 15.685 148.290 ;
    END
  END RBL[208]
  PIN RBL[209]
    ANTENNADIFFAREA 0.511400 ;
    PORT
      LAYER Metal4 ;
        RECT 10.165 148.660 19.075 149.660 ;
    END
  END RBL[209]
  PIN RBL[210]
    ANTENNADIFFAREA 0.511400 ;
    PORT
      LAYER Metal4 ;
        RECT 10.165 150.030 22.185 151.030 ;
    END
  END RBL[210]
  PIN RBL[211]
    ANTENNADIFFAREA 0.511400 ;
    PORT
      LAYER Metal4 ;
        RECT 10.165 151.400 25.295 152.400 ;
    END
  END RBL[211]
  PIN RBL[212]
    ANTENNADIFFAREA 0.511400 ;
    PORT
      LAYER Metal4 ;
        RECT 28.125 151.400 40.500 152.400 ;
    END
  END RBL[212]
  PIN RBL[213]
    ANTENNADIFFAREA 0.511400 ;
    PORT
      LAYER Metal4 ;
        RECT 31.235 150.030 40.500 151.030 ;
    END
  END RBL[213]
  PIN RBL[214]
    ANTENNADIFFAREA 0.511400 ;
    PORT
      LAYER Metal4 ;
        RECT 34.345 148.660 40.500 149.660 ;
    END
  END RBL[214]
  PIN RBL[215]
    ANTENNADIFFAREA 0.511400 ;
    PORT
      LAYER Metal4 ;
        RECT 37.455 147.290 40.500 148.290 ;
    END
  END RBL[215]
  PIN RBL[216]
    ANTENNADIFFAREA 0.511400 ;
    PORT
      LAYER Metal4 ;
        RECT 10.165 152.770 15.685 153.770 ;
    END
  END RBL[216]
  PIN RBL[217]
    ANTENNADIFFAREA 0.511400 ;
    PORT
      LAYER Metal4 ;
        RECT 10.165 154.140 19.075 155.140 ;
    END
  END RBL[217]
  PIN RBL[218]
    ANTENNADIFFAREA 0.511400 ;
    PORT
      LAYER Metal4 ;
        RECT 10.165 155.510 22.185 156.510 ;
    END
  END RBL[218]
  PIN RBL[219]
    ANTENNADIFFAREA 0.511400 ;
    PORT
      LAYER Metal4 ;
        RECT 10.165 156.880 25.295 157.880 ;
    END
  END RBL[219]
  PIN RBL[220]
    ANTENNADIFFAREA 0.511400 ;
    PORT
      LAYER Metal4 ;
        RECT 28.125 156.880 40.500 157.880 ;
    END
  END RBL[220]
  PIN RBL[221]
    ANTENNADIFFAREA 0.511400 ;
    PORT
      LAYER Metal4 ;
        RECT 31.235 155.510 40.500 156.510 ;
    END
  END RBL[221]
  PIN RBL[222]
    ANTENNADIFFAREA 0.511400 ;
    PORT
      LAYER Metal4 ;
        RECT 34.345 154.140 40.500 155.140 ;
    END
  END RBL[222]
  PIN RBL[223]
    ANTENNADIFFAREA 0.511400 ;
    PORT
      LAYER Metal4 ;
        RECT 37.455 152.770 40.500 153.770 ;
    END
  END RBL[223]
  PIN RBL[224]
    ANTENNADIFFAREA 0.511400 ;
    PORT
      LAYER Metal4 ;
        RECT 10.165 158.250 15.685 159.250 ;
    END
  END RBL[224]
  PIN RBL[225]
    ANTENNADIFFAREA 0.511400 ;
    PORT
      LAYER Metal4 ;
        RECT 10.165 159.620 19.075 160.620 ;
    END
  END RBL[225]
  PIN RBL[226]
    ANTENNADIFFAREA 0.511400 ;
    PORT
      LAYER Metal4 ;
        RECT 10.165 160.990 22.185 161.990 ;
    END
  END RBL[226]
  PIN RBL[227]
    ANTENNADIFFAREA 0.511400 ;
    PORT
      LAYER Metal4 ;
        RECT 10.165 162.360 25.295 163.360 ;
    END
  END RBL[227]
  PIN RBL[228]
    ANTENNADIFFAREA 0.511400 ;
    PORT
      LAYER Metal4 ;
        RECT 28.125 162.360 40.500 163.360 ;
    END
  END RBL[228]
  PIN RBL[229]
    ANTENNADIFFAREA 0.511400 ;
    PORT
      LAYER Metal4 ;
        RECT 31.235 160.990 40.500 161.990 ;
    END
  END RBL[229]
  PIN RBL[230]
    ANTENNADIFFAREA 0.511400 ;
    PORT
      LAYER Metal4 ;
        RECT 34.345 159.620 40.500 160.620 ;
    END
  END RBL[230]
  PIN RBL[231]
    ANTENNADIFFAREA 0.511400 ;
    PORT
      LAYER Metal4 ;
        RECT 37.455 158.250 40.500 159.250 ;
    END
  END RBL[231]
  PIN RBL[232]
    ANTENNADIFFAREA 0.511400 ;
    PORT
      LAYER Metal4 ;
        RECT 10.165 163.730 15.685 164.730 ;
    END
  END RBL[232]
  PIN RBL[233]
    ANTENNADIFFAREA 0.511400 ;
    PORT
      LAYER Metal4 ;
        RECT 10.165 165.100 19.075 166.100 ;
    END
  END RBL[233]
  PIN RBL[234]
    ANTENNADIFFAREA 0.511400 ;
    PORT
      LAYER Metal4 ;
        RECT 10.165 166.470 22.185 167.470 ;
    END
  END RBL[234]
  PIN RBL[235]
    ANTENNADIFFAREA 0.511400 ;
    PORT
      LAYER Metal4 ;
        RECT 10.165 167.840 25.295 168.840 ;
    END
  END RBL[235]
  PIN RBL[236]
    ANTENNADIFFAREA 0.511400 ;
    PORT
      LAYER Metal4 ;
        RECT 28.125 167.840 40.500 168.840 ;
    END
  END RBL[236]
  PIN RBL[237]
    ANTENNADIFFAREA 0.511400 ;
    PORT
      LAYER Metal4 ;
        RECT 31.235 166.470 40.500 167.470 ;
    END
  END RBL[237]
  PIN RBL[238]
    ANTENNADIFFAREA 0.511400 ;
    PORT
      LAYER Metal4 ;
        RECT 34.345 165.100 40.500 166.100 ;
    END
  END RBL[238]
  PIN RBL[239]
    ANTENNADIFFAREA 0.511400 ;
    PORT
      LAYER Metal4 ;
        RECT 37.455 163.730 40.500 164.730 ;
    END
  END RBL[239]
  PIN RBL[240]
    ANTENNADIFFAREA 0.511400 ;
    PORT
      LAYER Metal4 ;
        RECT 10.165 169.210 15.685 170.210 ;
    END
  END RBL[240]
  PIN RBL[241]
    ANTENNADIFFAREA 0.511400 ;
    PORT
      LAYER Metal4 ;
        RECT 10.165 170.580 19.075 171.580 ;
    END
  END RBL[241]
  PIN RBL[242]
    ANTENNADIFFAREA 0.511400 ;
    PORT
      LAYER Metal4 ;
        RECT 10.165 171.950 22.185 172.950 ;
    END
  END RBL[242]
  PIN RBL[243]
    ANTENNADIFFAREA 0.511400 ;
    PORT
      LAYER Metal4 ;
        RECT 10.165 173.320 25.295 174.320 ;
    END
  END RBL[243]
  PIN RBL[244]
    ANTENNADIFFAREA 0.511400 ;
    PORT
      LAYER Metal4 ;
        RECT 28.125 173.320 40.500 174.320 ;
    END
  END RBL[244]
  PIN RBL[245]
    ANTENNADIFFAREA 0.511400 ;
    PORT
      LAYER Metal4 ;
        RECT 31.235 171.950 40.500 172.950 ;
    END
  END RBL[245]
  PIN RBL[246]
    ANTENNADIFFAREA 0.511400 ;
    PORT
      LAYER Metal4 ;
        RECT 34.345 170.580 40.500 171.580 ;
    END
  END RBL[246]
  PIN RBL[247]
    ANTENNADIFFAREA 0.511400 ;
    PORT
      LAYER Metal4 ;
        RECT 37.455 169.210 40.500 170.210 ;
    END
  END RBL[247]
  PIN RBL[248]
    ANTENNADIFFAREA 0.511400 ;
    PORT
      LAYER Metal4 ;
        RECT 10.165 174.690 15.685 175.690 ;
    END
  END RBL[248]
  PIN RBL[249]
    ANTENNADIFFAREA 0.511400 ;
    PORT
      LAYER Metal4 ;
        RECT 10.165 176.060 19.075 177.060 ;
    END
  END RBL[249]
  PIN RBL[250]
    ANTENNADIFFAREA 0.511400 ;
    PORT
      LAYER Metal4 ;
        RECT 10.165 177.430 22.185 178.430 ;
    END
  END RBL[250]
  PIN RBL[251]
    ANTENNADIFFAREA 0.511400 ;
    PORT
      LAYER Metal4 ;
        RECT 10.165 178.800 25.295 179.800 ;
    END
  END RBL[251]
  PIN RBL[252]
    ANTENNADIFFAREA 0.511400 ;
    PORT
      LAYER Metal4 ;
        RECT 28.125 178.800 40.500 179.800 ;
    END
  END RBL[252]
  PIN RBL[253]
    ANTENNADIFFAREA 0.511400 ;
    PORT
      LAYER Metal4 ;
        RECT 31.235 177.430 40.500 178.430 ;
    END
  END RBL[253]
  PIN RBL[254]
    ANTENNADIFFAREA 0.511400 ;
    PORT
      LAYER Metal4 ;
        RECT 34.345 176.060 40.500 177.060 ;
    END
  END RBL[254]
  PIN RBL[255]
    ANTENNADIFFAREA 0.511400 ;
    PORT
      LAYER Metal4 ;
        RECT 37.455 174.690 40.500 175.690 ;
    END
  END RBL[255]
  PIN VDD
    USE POWER ;
    PORT
      LAYER Metal3 ;
        RECT 41.425 174.355 42.385 177.890 ;
    END
    PORT
      LAYER Metal3 ;
        RECT 41.425 168.875 42.385 173.565 ;
    END
    PORT
      LAYER Metal3 ;
        RECT 41.425 163.395 42.385 168.085 ;
    END
    PORT
      LAYER Metal3 ;
        RECT 41.425 157.915 42.385 162.605 ;
    END
    PORT
      LAYER Metal3 ;
        RECT 41.425 152.435 42.385 157.125 ;
    END
    PORT
      LAYER Metal3 ;
        RECT 41.425 146.955 42.385 151.645 ;
    END
    PORT
      LAYER Metal3 ;
        RECT 41.425 141.475 42.385 146.165 ;
    END
    PORT
      LAYER Metal3 ;
        RECT 41.425 135.995 42.385 140.685 ;
    END
    PORT
      LAYER Metal3 ;
        RECT 41.425 130.515 42.385 135.205 ;
    END
    PORT
      LAYER Metal3 ;
        RECT 41.425 125.035 42.385 129.725 ;
    END
    PORT
      LAYER Metal3 ;
        RECT 41.425 119.555 42.385 124.245 ;
    END
    PORT
      LAYER Metal3 ;
        RECT 41.425 114.075 42.385 118.765 ;
    END
    PORT
      LAYER Metal3 ;
        RECT 41.425 108.595 42.385 113.285 ;
    END
    PORT
      LAYER Metal3 ;
        RECT 41.425 103.115 42.385 107.805 ;
    END
    PORT
      LAYER Metal3 ;
        RECT 41.425 97.635 42.385 102.325 ;
    END
    PORT
      LAYER Metal3 ;
        RECT 41.425 92.155 42.385 96.845 ;
    END
    PORT
      LAYER Metal3 ;
        RECT 41.425 86.675 42.385 91.365 ;
    END
    PORT
      LAYER Metal3 ;
        RECT 41.425 81.195 42.385 85.885 ;
    END
    PORT
      LAYER Metal3 ;
        RECT 41.425 75.715 42.385 80.405 ;
    END
    PORT
      LAYER Metal3 ;
        RECT 41.425 70.235 42.385 74.925 ;
    END
    PORT
      LAYER Metal3 ;
        RECT 41.425 64.755 42.385 69.445 ;
    END
    PORT
      LAYER Metal3 ;
        RECT 41.425 59.275 42.385 63.965 ;
    END
    PORT
      LAYER Metal3 ;
        RECT 41.425 53.795 42.385 58.485 ;
    END
    PORT
      LAYER Metal3 ;
        RECT 41.425 48.315 42.385 53.005 ;
    END
    PORT
      LAYER Metal3 ;
        RECT 41.425 42.835 42.385 47.525 ;
    END
    PORT
      LAYER Metal3 ;
        RECT 41.425 37.355 42.385 42.045 ;
    END
    PORT
      LAYER Metal3 ;
        RECT 41.425 31.875 42.385 36.565 ;
    END
    PORT
      LAYER Metal3 ;
        RECT 41.425 26.395 42.385 31.085 ;
    END
    PORT
      LAYER Metal3 ;
        RECT 41.425 20.915 42.385 25.605 ;
    END
    PORT
      LAYER Metal3 ;
        RECT 41.425 15.435 42.385 20.125 ;
    END
    PORT
      LAYER Metal3 ;
        RECT 41.425 9.955 42.385 14.645 ;
    END
    PORT
      LAYER Metal3 ;
        RECT 41.425 4.475 42.385 9.165 ;
    END
    PORT
      LAYER Metal3 ;
        RECT 41.425 0.080 42.385 3.685 ;
    END
    PORT
      LAYER Metal3 ;
        RECT 7.500 163.405 8.670 168.075 ;
    END
    PORT
      LAYER Metal3 ;
        RECT 7.500 157.925 8.670 162.595 ;
    END
    PORT
      LAYER Metal3 ;
        RECT 7.500 152.445 8.670 157.115 ;
    END
    PORT
      LAYER Metal3 ;
        RECT 7.500 146.965 8.670 151.635 ;
    END
    PORT
      LAYER Metal3 ;
        RECT 7.500 141.485 8.670 146.155 ;
    END
    PORT
      LAYER Metal3 ;
        RECT 7.500 136.005 8.670 140.675 ;
    END
    PORT
      LAYER Metal3 ;
        RECT 7.500 130.525 8.670 135.195 ;
    END
    PORT
      LAYER Metal3 ;
        RECT 7.500 125.045 8.670 129.715 ;
    END
    PORT
      LAYER Metal3 ;
        RECT 7.500 119.565 8.670 124.235 ;
    END
    PORT
      LAYER Metal3 ;
        RECT 7.500 114.085 8.670 118.755 ;
    END
    PORT
      LAYER Metal3 ;
        RECT 7.500 108.605 8.670 113.275 ;
    END
    PORT
      LAYER Metal3 ;
        RECT 7.500 103.125 8.670 107.795 ;
    END
    PORT
      LAYER Metal3 ;
        RECT 7.500 97.645 8.670 102.315 ;
    END
    PORT
      LAYER Metal3 ;
        RECT 7.500 92.165 8.670 96.835 ;
    END
    PORT
      LAYER Metal3 ;
        RECT 7.500 86.685 8.670 91.355 ;
    END
    PORT
      LAYER Metal3 ;
        RECT 7.500 81.205 8.670 85.875 ;
    END
    PORT
      LAYER Metal3 ;
        RECT 7.500 75.725 8.670 80.395 ;
    END
    PORT
      LAYER Metal3 ;
        RECT 7.500 70.245 8.670 74.915 ;
    END
    PORT
      LAYER Metal3 ;
        RECT 7.500 64.765 8.670 69.435 ;
    END
    PORT
      LAYER Metal3 ;
        RECT 7.500 59.285 8.670 63.955 ;
    END
    PORT
      LAYER Metal3 ;
        RECT 7.500 53.805 8.670 58.475 ;
    END
    PORT
      LAYER Metal3 ;
        RECT 7.500 48.325 8.670 52.995 ;
    END
    PORT
      LAYER Metal3 ;
        RECT 7.500 42.845 8.670 47.515 ;
    END
    PORT
      LAYER Metal3 ;
        RECT 7.500 37.365 8.670 42.035 ;
    END
    PORT
      LAYER Metal3 ;
        RECT 7.500 31.885 8.670 36.555 ;
    END
    PORT
      LAYER Metal3 ;
        RECT 7.500 26.405 8.670 31.075 ;
    END
    PORT
      LAYER Metal3 ;
        RECT 7.500 20.925 8.670 25.595 ;
    END
    PORT
      LAYER Metal3 ;
        RECT 7.500 15.445 8.670 20.115 ;
    END
    PORT
      LAYER Metal3 ;
        RECT 7.500 9.965 8.670 14.640 ;
    END
    PORT
      LAYER Metal3 ;
        RECT 7.500 4.240 8.670 8.035 ;
    END
    PORT
      LAYER Metal3 ;
        RECT 7.500 0.110 8.670 3.960 ;
    END
    PORT
      LAYER Metal3 ;
        RECT 7.500 168.885 8.670 173.555 ;
    END
    PORT
      LAYER Metal3 ;
        RECT 7.500 174.365 8.670 177.890 ;
    END
  END VDD
  PIN VSS
    USE GROUND ;
    PORT
      LAYER Metal3 ;
        RECT 42.725 0.080 43.870 2.575 ;
    END
    PORT
      LAYER Metal3 ;
        RECT 42.725 3.375 43.870 8.055 ;
    END
    PORT
      LAYER Metal3 ;
        RECT 42.725 8.855 43.870 13.535 ;
    END
    PORT
      LAYER Metal3 ;
        RECT 42.725 14.335 43.870 19.015 ;
    END
    PORT
      LAYER Metal3 ;
        RECT 42.725 19.815 43.870 24.495 ;
    END
    PORT
      LAYER Metal3 ;
        RECT 42.725 25.295 43.870 29.975 ;
    END
    PORT
      LAYER Metal3 ;
        RECT 42.725 30.775 43.870 35.455 ;
    END
    PORT
      LAYER Metal3 ;
        RECT 42.725 36.255 43.870 40.935 ;
    END
    PORT
      LAYER Metal3 ;
        RECT 42.725 41.735 43.870 46.415 ;
    END
    PORT
      LAYER Metal3 ;
        RECT 42.725 47.215 43.870 51.895 ;
    END
    PORT
      LAYER Metal3 ;
        RECT 42.725 52.695 43.870 57.375 ;
    END
    PORT
      LAYER Metal3 ;
        RECT 42.725 58.175 43.870 62.855 ;
    END
    PORT
      LAYER Metal3 ;
        RECT 42.725 63.655 43.870 68.335 ;
    END
    PORT
      LAYER Metal3 ;
        RECT 42.725 69.135 43.870 73.815 ;
    END
    PORT
      LAYER Metal3 ;
        RECT 42.725 74.615 43.870 79.295 ;
    END
    PORT
      LAYER Metal3 ;
        RECT 42.725 80.095 43.870 84.775 ;
    END
    PORT
      LAYER Metal3 ;
        RECT 42.725 85.575 43.870 90.255 ;
    END
    PORT
      LAYER Metal3 ;
        RECT 42.725 91.055 43.870 95.735 ;
    END
    PORT
      LAYER Metal3 ;
        RECT 42.725 96.535 43.870 101.215 ;
    END
    PORT
      LAYER Metal3 ;
        RECT 42.725 102.015 43.870 106.695 ;
    END
    PORT
      LAYER Metal3 ;
        RECT 42.725 107.495 43.870 112.175 ;
    END
    PORT
      LAYER Metal3 ;
        RECT 42.725 112.975 43.870 117.655 ;
    END
    PORT
      LAYER Metal3 ;
        RECT 42.725 118.455 43.870 123.135 ;
    END
    PORT
      LAYER Metal3 ;
        RECT 42.725 123.935 43.870 128.615 ;
    END
    PORT
      LAYER Metal3 ;
        RECT 42.725 129.415 43.870 134.095 ;
    END
    PORT
      LAYER Metal3 ;
        RECT 42.725 134.895 43.870 139.575 ;
    END
    PORT
      LAYER Metal3 ;
        RECT 42.725 140.375 43.870 145.055 ;
    END
    PORT
      LAYER Metal3 ;
        RECT 42.725 145.855 43.870 150.535 ;
    END
    PORT
      LAYER Metal3 ;
        RECT 42.725 151.335 43.870 156.015 ;
    END
    PORT
      LAYER Metal3 ;
        RECT 42.725 156.815 43.870 161.495 ;
    END
    PORT
      LAYER Metal3 ;
        RECT 42.725 162.295 43.870 166.975 ;
    END
    PORT
      LAYER Metal3 ;
        RECT 42.725 167.775 43.870 172.455 ;
    END
    PORT
      LAYER Metal3 ;
        RECT 42.730 173.255 43.870 177.895 ;
    END
    PORT
      LAYER Metal3 ;
        RECT 5.925 0.100 7.155 8.060 ;
    END
    PORT
      LAYER Metal3 ;
        RECT 5.925 8.835 7.155 13.540 ;
    END
    PORT
      LAYER Metal3 ;
        RECT 5.925 14.315 7.155 19.020 ;
    END
    PORT
      LAYER Metal3 ;
        RECT 5.925 19.795 7.155 24.500 ;
    END
    PORT
      LAYER Metal3 ;
        RECT 5.925 25.275 7.155 29.980 ;
    END
    PORT
      LAYER Metal3 ;
        RECT 5.925 30.755 7.155 35.460 ;
    END
    PORT
      LAYER Metal3 ;
        RECT 5.925 36.235 7.155 40.940 ;
    END
    PORT
      LAYER Metal3 ;
        RECT 5.925 41.715 7.155 46.420 ;
    END
    PORT
      LAYER Metal3 ;
        RECT 5.925 47.195 7.155 51.900 ;
    END
    PORT
      LAYER Metal3 ;
        RECT 5.925 52.675 7.155 57.380 ;
    END
    PORT
      LAYER Metal3 ;
        RECT 5.925 58.155 7.155 62.860 ;
    END
    PORT
      LAYER Metal3 ;
        RECT 5.925 63.635 7.155 68.340 ;
    END
    PORT
      LAYER Metal3 ;
        RECT 5.925 69.115 7.155 73.820 ;
    END
    PORT
      LAYER Metal3 ;
        RECT 5.925 74.595 7.155 79.300 ;
    END
    PORT
      LAYER Metal3 ;
        RECT 5.925 80.075 7.155 84.780 ;
    END
    PORT
      LAYER Metal3 ;
        RECT 5.925 85.555 7.155 90.260 ;
    END
    PORT
      LAYER Metal3 ;
        RECT 5.925 91.035 7.155 95.740 ;
    END
    PORT
      LAYER Metal3 ;
        RECT 5.925 96.515 7.155 101.220 ;
    END
    PORT
      LAYER Metal3 ;
        RECT 5.925 101.995 7.155 106.700 ;
    END
    PORT
      LAYER Metal3 ;
        RECT 5.925 107.475 7.155 112.180 ;
    END
    PORT
      LAYER Metal3 ;
        RECT 5.925 112.955 7.155 117.660 ;
    END
    PORT
      LAYER Metal3 ;
        RECT 5.925 118.435 7.155 123.140 ;
    END
    PORT
      LAYER Metal3 ;
        RECT 5.925 123.915 7.155 128.620 ;
    END
    PORT
      LAYER Metal3 ;
        RECT 5.925 129.395 7.155 134.100 ;
    END
    PORT
      LAYER Metal3 ;
        RECT 5.925 134.875 7.155 139.580 ;
    END
    PORT
      LAYER Metal3 ;
        RECT 5.925 140.355 7.155 145.060 ;
    END
    PORT
      LAYER Metal3 ;
        RECT 5.925 145.835 7.155 150.540 ;
    END
    PORT
      LAYER Metal3 ;
        RECT 5.925 151.315 7.155 156.020 ;
    END
    PORT
      LAYER Metal3 ;
        RECT 5.925 156.795 7.155 161.500 ;
    END
    PORT
      LAYER Metal3 ;
        RECT 5.925 162.275 7.155 166.980 ;
    END
    PORT
      LAYER Metal3 ;
        RECT 5.925 167.755 7.155 172.460 ;
    END
    PORT
      LAYER Metal3 ;
        RECT 5.925 173.235 7.155 177.890 ;
    END
  END VSS
  PIN WBL[0]
    ANTENNADIFFAREA 5.459200 ;
    PORT
      LAYER Metal3 ;
        RECT 14.485 0.160 15.445 0.855 ;
    END
    PORT
      LAYER Metal3 ;
        RECT 14.495 180.145 15.455 180.835 ;
    END
  END WBL[0]
  PIN WBL[1]
    ANTENNADIFFAREA 5.459200 ;
    PORT
      LAYER Metal3 ;
        RECT 17.605 0.160 18.565 0.855 ;
    END
    PORT
      LAYER Metal3 ;
        RECT 17.605 180.145 18.565 180.835 ;
    END
  END WBL[1]
  PIN WBL[2]
    ANTENNADIFFAREA 5.459200 ;
    PORT
      LAYER Metal3 ;
        RECT 20.715 0.160 21.675 0.855 ;
    END
    PORT
      LAYER Metal3 ;
        RECT 20.715 180.145 21.675 180.835 ;
    END
  END WBL[2]
  PIN WBL[3]
    ANTENNADIFFAREA 5.459200 ;
    PORT
      LAYER Metal3 ;
        RECT 23.825 0.160 24.785 0.855 ;
    END
    PORT
      LAYER Metal3 ;
        RECT 23.825 180.145 24.785 180.835 ;
    END
  END WBL[3]
  PIN WBL[4]
    ANTENNADIFFAREA 5.459200 ;
    PORT
      LAYER Metal3 ;
        RECT 26.935 0.160 27.895 0.855 ;
    END
    PORT
      LAYER Metal3 ;
        RECT 26.935 180.145 27.895 180.835 ;
    END
  END WBL[4]
  PIN WBL[5]
    ANTENNADIFFAREA 5.459200 ;
    PORT
      LAYER Metal3 ;
        RECT 30.045 0.160 31.005 0.855 ;
    END
    PORT
      LAYER Metal3 ;
        RECT 30.045 180.145 31.005 180.835 ;
    END
  END WBL[5]
  PIN WBL[6]
    ANTENNADIFFAREA 5.459200 ;
    PORT
      LAYER Metal3 ;
        RECT 33.155 0.160 34.115 0.855 ;
    END
    PORT
      LAYER Metal3 ;
        RECT 33.155 180.145 34.115 180.835 ;
    END
  END WBL[6]
  PIN WBL[7]
    ANTENNADIFFAREA 5.459200 ;
    PORT
      LAYER Metal3 ;
        RECT 36.265 0.160 37.225 0.855 ;
    END
    PORT
      LAYER Metal3 ;
        RECT 36.265 180.145 37.225 180.835 ;
    END
  END WBL[7]
  PIN WBLB[0]
    ANTENNADIFFAREA 7.558400 ;
    PORT
      LAYER Metal3 ;
        RECT 13.225 0.155 14.185 0.850 ;
    END
    PORT
      LAYER Metal3 ;
        RECT 13.240 180.140 14.200 180.835 ;
    END
  END WBLB[0]
  PIN WBLB[1]
    ANTENNADIFFAREA 7.558400 ;
    PORT
      LAYER Metal3 ;
        RECT 16.335 0.155 17.295 0.850 ;
    END
    PORT
      LAYER Metal3 ;
        RECT 16.350 180.140 17.310 180.835 ;
    END
  END WBLB[1]
  PIN WBLB[2]
    ANTENNADIFFAREA 7.558400 ;
    PORT
      LAYER Metal3 ;
        RECT 19.445 0.155 20.405 0.850 ;
    END
    PORT
      LAYER Metal3 ;
        RECT 19.460 180.140 20.420 180.835 ;
    END
  END WBLB[2]
  PIN WBLB[3]
    ANTENNADIFFAREA 7.558400 ;
    PORT
      LAYER Metal3 ;
        RECT 22.555 0.155 23.515 0.850 ;
    END
    PORT
      LAYER Metal3 ;
        RECT 22.570 180.140 23.530 180.835 ;
    END
  END WBLB[3]
  PIN WBLB[4]
    ANTENNADIFFAREA 7.558400 ;
    PORT
      LAYER Metal3 ;
        RECT 25.665 0.155 26.625 0.850 ;
    END
    PORT
      LAYER Metal3 ;
        RECT 25.680 180.140 26.640 180.835 ;
    END
  END WBLB[4]
  PIN WBLB[5]
    ANTENNADIFFAREA 7.558400 ;
    PORT
      LAYER Metal3 ;
        RECT 28.775 0.155 29.735 0.850 ;
    END
    PORT
      LAYER Metal3 ;
        RECT 28.790 180.140 29.750 180.835 ;
    END
  END WBLB[5]
  PIN WBLB[6]
    ANTENNADIFFAREA 7.558400 ;
    PORT
      LAYER Metal3 ;
        RECT 31.885 0.155 32.845 0.850 ;
    END
    PORT
      LAYER Metal3 ;
        RECT 31.900 180.140 32.860 180.835 ;
    END
  END WBLB[6]
  PIN WBLB[7]
    ANTENNADIFFAREA 7.558400 ;
    PORT
      LAYER Metal3 ;
        RECT 34.995 0.155 35.955 0.850 ;
    END
    PORT
      LAYER Metal3 ;
        RECT 35.010 180.140 35.970 180.835 ;
    END
  END WBLB[7]
  PIN WL[0]
    ANTENNAGATEAREA 1.433600 ;
    PORT
      LAYER Metal1 ;
        RECT 3.555 1.270 13.210 2.290 ;
    END
  END WL[0]
  PIN WL[1]
    ANTENNAGATEAREA 1.433600 ;
    PORT
      LAYER Metal1 ;
        RECT 3.555 6.750 13.040 7.770 ;
    END
  END WL[1]
  PIN WL[2]
    ANTENNAGATEAREA 1.433600 ;
    PORT
      LAYER Metal1 ;
        RECT 3.555 12.230 13.040 13.250 ;
    END
  END WL[2]
  PIN WL[3]
    ANTENNAGATEAREA 1.433600 ;
    PORT
      LAYER Metal1 ;
        RECT 3.555 17.710 13.040 18.730 ;
    END
  END WL[3]
  PIN WL[4]
    ANTENNAGATEAREA 1.433600 ;
    PORT
      LAYER Metal1 ;
        RECT 3.555 23.190 13.040 24.210 ;
    END
  END WL[4]
  PIN WL[5]
    ANTENNAGATEAREA 1.433600 ;
    PORT
      LAYER Metal1 ;
        RECT 3.555 28.670 13.040 29.690 ;
    END
  END WL[5]
  PIN WL[6]
    ANTENNAGATEAREA 1.433600 ;
    PORT
      LAYER Metal1 ;
        RECT 3.555 34.150 13.040 35.170 ;
    END
  END WL[6]
  PIN WL[7]
    ANTENNAGATEAREA 1.433600 ;
    PORT
      LAYER Metal1 ;
        RECT 3.555 39.630 13.040 40.650 ;
    END
  END WL[7]
  PIN WL[8]
    ANTENNAGATEAREA 1.433600 ;
    PORT
      LAYER Metal1 ;
        RECT 3.555 45.110 13.040 46.130 ;
    END
  END WL[8]
  PIN WL[9]
    ANTENNAGATEAREA 1.433600 ;
    PORT
      LAYER Metal1 ;
        RECT 3.555 50.590 13.040 51.610 ;
    END
  END WL[9]
  PIN WL[10]
    ANTENNAGATEAREA 1.433600 ;
    PORT
      LAYER Metal1 ;
        RECT 3.555 56.070 13.040 57.090 ;
    END
  END WL[10]
  PIN WL[11]
    ANTENNAGATEAREA 1.433600 ;
    PORT
      LAYER Metal1 ;
        RECT 3.555 61.550 13.040 62.570 ;
    END
  END WL[11]
  PIN WL[12]
    ANTENNAGATEAREA 1.433600 ;
    PORT
      LAYER Metal1 ;
        RECT 3.555 67.030 13.040 68.050 ;
    END
  END WL[12]
  PIN WL[13]
    ANTENNAGATEAREA 1.433600 ;
    PORT
      LAYER Metal1 ;
        RECT 3.555 72.510 13.040 73.530 ;
    END
  END WL[13]
  PIN WL[14]
    ANTENNAGATEAREA 1.433600 ;
    PORT
      LAYER Metal1 ;
        RECT 3.555 77.990 13.040 79.010 ;
    END
  END WL[14]
  PIN WL[15]
    ANTENNAGATEAREA 1.433600 ;
    PORT
      LAYER Metal1 ;
        RECT 3.555 83.470 13.040 84.490 ;
    END
  END WL[15]
  PIN WL[16]
    ANTENNAGATEAREA 1.433600 ;
    PORT
      LAYER Metal1 ;
        RECT 3.555 88.950 13.040 89.970 ;
    END
  END WL[16]
  PIN WL[17]
    ANTENNAGATEAREA 1.433600 ;
    PORT
      LAYER Metal1 ;
        RECT 3.555 94.430 13.040 95.450 ;
    END
  END WL[17]
  PIN WL[18]
    ANTENNAGATEAREA 1.433600 ;
    PORT
      LAYER Metal1 ;
        RECT 3.555 99.910 13.040 100.930 ;
    END
  END WL[18]
  PIN WL[19]
    ANTENNAGATEAREA 1.433600 ;
    PORT
      LAYER Metal1 ;
        RECT 3.555 105.390 13.040 106.410 ;
    END
  END WL[19]
  PIN WL[20]
    ANTENNAGATEAREA 1.433600 ;
    PORT
      LAYER Metal1 ;
        RECT 3.555 110.870 13.040 111.890 ;
    END
  END WL[20]
  PIN WL[21]
    ANTENNAGATEAREA 1.433600 ;
    PORT
      LAYER Metal1 ;
        RECT 3.555 116.350 13.040 117.370 ;
    END
  END WL[21]
  PIN WL[22]
    ANTENNAGATEAREA 1.433600 ;
    PORT
      LAYER Metal1 ;
        RECT 3.555 121.830 13.040 122.850 ;
    END
  END WL[22]
  PIN WL[23]
    ANTENNAGATEAREA 1.433600 ;
    PORT
      LAYER Metal1 ;
        RECT 3.555 127.310 13.040 128.330 ;
    END
  END WL[23]
  PIN WL[24]
    ANTENNAGATEAREA 1.433600 ;
    PORT
      LAYER Metal1 ;
        RECT 3.555 132.790 13.040 133.810 ;
    END
  END WL[24]
  PIN WL[25]
    ANTENNAGATEAREA 1.433600 ;
    PORT
      LAYER Metal1 ;
        RECT 3.555 138.270 13.040 139.290 ;
    END
  END WL[25]
  PIN WL[26]
    ANTENNAGATEAREA 1.433600 ;
    PORT
      LAYER Metal1 ;
        RECT 3.555 143.750 13.040 144.770 ;
    END
  END WL[26]
  PIN WL[27]
    ANTENNAGATEAREA 1.433600 ;
    PORT
      LAYER Metal1 ;
        RECT 3.555 149.230 13.040 150.250 ;
    END
  END WL[27]
  PIN WL[28]
    ANTENNAGATEAREA 1.433600 ;
    PORT
      LAYER Metal1 ;
        RECT 3.555 154.710 13.040 155.730 ;
    END
  END WL[28]
  PIN WL[29]
    ANTENNAGATEAREA 1.433600 ;
    PORT
      LAYER Metal1 ;
        RECT 3.555 160.190 13.040 161.210 ;
    END
  END WL[29]
  PIN WL[30]
    ANTENNAGATEAREA 1.433600 ;
    PORT
      LAYER Metal1 ;
        RECT 3.555 165.670 13.040 166.690 ;
    END
  END WL[30]
  PIN WL[31]
    ANTENNAGATEAREA 1.433600 ;
    PORT
      LAYER Metal1 ;
        RECT 3.555 171.150 13.040 172.170 ;
    END
  END WL[31]
  OBS
      LAYER Nwell ;
        RECT 11.545 1.350 39.265 176.710 ;
      LAYER Metal1 ;
        RECT 11.665 176.530 39.145 176.710 ;
        RECT 11.665 174.630 38.845 176.530 ;
        RECT 11.665 172.470 39.145 174.630 ;
        RECT 13.340 171.050 39.145 172.470 ;
        RECT 13.340 170.850 38.845 171.050 ;
        RECT 11.665 169.150 38.845 170.850 ;
        RECT 11.665 166.990 39.145 169.150 ;
        RECT 13.340 165.570 39.145 166.990 ;
        RECT 13.340 165.370 38.845 165.570 ;
        RECT 11.665 163.670 38.845 165.370 ;
        RECT 11.665 161.510 39.145 163.670 ;
        RECT 13.340 160.090 39.145 161.510 ;
        RECT 13.340 159.890 38.845 160.090 ;
        RECT 11.665 158.190 38.845 159.890 ;
        RECT 11.665 156.030 39.145 158.190 ;
        RECT 13.340 154.610 39.145 156.030 ;
        RECT 13.340 154.410 38.845 154.610 ;
        RECT 11.665 152.710 38.845 154.410 ;
        RECT 11.665 150.550 39.145 152.710 ;
        RECT 13.340 149.130 39.145 150.550 ;
        RECT 13.340 148.930 38.845 149.130 ;
        RECT 11.665 147.230 38.845 148.930 ;
        RECT 11.665 145.070 39.145 147.230 ;
        RECT 13.340 143.650 39.145 145.070 ;
        RECT 13.340 143.450 38.845 143.650 ;
        RECT 11.665 141.750 38.845 143.450 ;
        RECT 11.665 139.590 39.145 141.750 ;
        RECT 13.340 138.170 39.145 139.590 ;
        RECT 13.340 137.970 38.845 138.170 ;
        RECT 11.665 136.270 38.845 137.970 ;
        RECT 11.665 134.110 39.145 136.270 ;
        RECT 13.340 132.690 39.145 134.110 ;
        RECT 13.340 132.490 38.845 132.690 ;
        RECT 11.665 130.790 38.845 132.490 ;
        RECT 11.665 128.630 39.145 130.790 ;
        RECT 13.340 127.210 39.145 128.630 ;
        RECT 13.340 127.010 38.845 127.210 ;
        RECT 11.665 125.310 38.845 127.010 ;
        RECT 11.665 123.150 39.145 125.310 ;
        RECT 13.340 121.730 39.145 123.150 ;
        RECT 13.340 121.530 38.845 121.730 ;
        RECT 11.665 119.830 38.845 121.530 ;
        RECT 11.665 117.670 39.145 119.830 ;
        RECT 13.340 116.250 39.145 117.670 ;
        RECT 13.340 116.050 38.845 116.250 ;
        RECT 11.665 114.350 38.845 116.050 ;
        RECT 11.665 112.190 39.145 114.350 ;
        RECT 13.340 110.770 39.145 112.190 ;
        RECT 13.340 110.570 38.845 110.770 ;
        RECT 11.665 108.870 38.845 110.570 ;
        RECT 11.665 106.710 39.145 108.870 ;
        RECT 13.340 105.290 39.145 106.710 ;
        RECT 13.340 105.090 38.845 105.290 ;
        RECT 11.665 103.390 38.845 105.090 ;
        RECT 11.665 101.230 39.145 103.390 ;
        RECT 13.340 99.810 39.145 101.230 ;
        RECT 13.340 99.610 38.845 99.810 ;
        RECT 11.665 97.910 38.845 99.610 ;
        RECT 11.665 95.750 39.145 97.910 ;
        RECT 13.340 94.330 39.145 95.750 ;
        RECT 13.340 94.130 38.845 94.330 ;
        RECT 11.665 92.430 38.845 94.130 ;
        RECT 11.665 90.270 39.145 92.430 ;
        RECT 13.340 88.850 39.145 90.270 ;
        RECT 13.340 88.650 38.845 88.850 ;
        RECT 11.665 86.950 38.845 88.650 ;
        RECT 11.665 84.790 39.145 86.950 ;
        RECT 13.340 83.370 39.145 84.790 ;
        RECT 13.340 83.170 38.845 83.370 ;
        RECT 11.665 81.470 38.845 83.170 ;
        RECT 11.665 79.310 39.145 81.470 ;
        RECT 13.340 77.890 39.145 79.310 ;
        RECT 13.340 77.690 38.845 77.890 ;
        RECT 11.665 75.990 38.845 77.690 ;
        RECT 11.665 73.830 39.145 75.990 ;
        RECT 13.340 72.410 39.145 73.830 ;
        RECT 13.340 72.210 38.845 72.410 ;
        RECT 11.665 70.510 38.845 72.210 ;
        RECT 11.665 68.350 39.145 70.510 ;
        RECT 13.340 66.930 39.145 68.350 ;
        RECT 13.340 66.730 38.845 66.930 ;
        RECT 11.665 65.030 38.845 66.730 ;
        RECT 11.665 62.870 39.145 65.030 ;
        RECT 13.340 61.450 39.145 62.870 ;
        RECT 13.340 61.250 38.845 61.450 ;
        RECT 11.665 59.550 38.845 61.250 ;
        RECT 11.665 57.390 39.145 59.550 ;
        RECT 13.340 55.970 39.145 57.390 ;
        RECT 13.340 55.770 38.845 55.970 ;
        RECT 11.665 54.070 38.845 55.770 ;
        RECT 11.665 51.910 39.145 54.070 ;
        RECT 13.340 50.490 39.145 51.910 ;
        RECT 13.340 50.290 38.845 50.490 ;
        RECT 11.665 48.590 38.845 50.290 ;
        RECT 11.665 46.430 39.145 48.590 ;
        RECT 13.340 45.010 39.145 46.430 ;
        RECT 13.340 44.810 38.845 45.010 ;
        RECT 11.665 43.110 38.845 44.810 ;
        RECT 11.665 40.950 39.145 43.110 ;
        RECT 13.340 39.530 39.145 40.950 ;
        RECT 13.340 39.330 38.845 39.530 ;
        RECT 11.665 37.630 38.845 39.330 ;
        RECT 11.665 35.470 39.145 37.630 ;
        RECT 13.340 34.050 39.145 35.470 ;
        RECT 13.340 33.850 38.845 34.050 ;
        RECT 11.665 32.150 38.845 33.850 ;
        RECT 11.665 29.990 39.145 32.150 ;
        RECT 13.340 28.570 39.145 29.990 ;
        RECT 13.340 28.370 38.845 28.570 ;
        RECT 11.665 26.670 38.845 28.370 ;
        RECT 11.665 24.510 39.145 26.670 ;
        RECT 13.340 23.090 39.145 24.510 ;
        RECT 13.340 22.890 38.845 23.090 ;
        RECT 11.665 21.190 38.845 22.890 ;
        RECT 11.665 19.030 39.145 21.190 ;
        RECT 13.340 17.610 39.145 19.030 ;
        RECT 13.340 17.410 38.845 17.610 ;
        RECT 11.665 15.710 38.845 17.410 ;
        RECT 11.665 13.550 39.145 15.710 ;
        RECT 13.340 12.130 39.145 13.550 ;
        RECT 13.340 11.930 38.845 12.130 ;
        RECT 11.665 10.230 38.845 11.930 ;
        RECT 11.665 8.070 39.145 10.230 ;
        RECT 13.340 6.650 39.145 8.070 ;
        RECT 13.340 6.450 38.845 6.650 ;
        RECT 11.665 4.750 38.845 6.450 ;
        RECT 11.665 2.590 39.145 4.750 ;
        RECT 13.510 1.350 39.145 2.590 ;
      LAYER Metal2 ;
        RECT 5.925 1.380 43.870 176.285 ;
      LAYER Metal3 ;
        RECT 5.925 179.840 12.940 180.145 ;
        RECT 15.755 179.845 16.050 180.145 ;
        RECT 18.865 179.845 19.160 180.145 ;
        RECT 21.975 179.845 22.270 180.145 ;
        RECT 25.085 179.845 25.380 180.145 ;
        RECT 28.195 179.845 28.490 180.145 ;
        RECT 31.305 179.845 31.600 180.145 ;
        RECT 34.415 179.845 34.710 180.145 ;
        RECT 37.525 179.845 43.870 180.145 ;
        RECT 14.500 179.840 16.050 179.845 ;
        RECT 17.610 179.840 19.160 179.845 ;
        RECT 20.720 179.840 22.270 179.845 ;
        RECT 23.830 179.840 25.380 179.845 ;
        RECT 26.940 179.840 28.490 179.845 ;
        RECT 30.050 179.840 31.600 179.845 ;
        RECT 33.160 179.840 34.710 179.845 ;
        RECT 36.270 179.840 43.870 179.845 ;
        RECT 5.925 178.195 43.870 179.840 ;
        RECT 5.925 178.190 42.430 178.195 ;
        RECT 8.970 174.065 41.125 178.190 ;
        RECT 7.455 174.055 41.125 174.065 ;
        RECT 7.455 173.865 42.430 174.055 ;
        RECT 7.455 173.855 41.125 173.865 ;
        RECT 5.925 172.760 7.200 172.935 ;
        RECT 8.970 168.585 41.125 173.855 ;
        RECT 42.685 172.755 43.870 172.955 ;
        RECT 7.455 168.575 41.125 168.585 ;
        RECT 7.455 168.385 42.425 168.575 ;
        RECT 7.455 168.375 41.125 168.385 ;
        RECT 5.925 167.280 7.200 167.455 ;
        RECT 8.970 163.105 41.125 168.375 ;
        RECT 42.685 167.275 43.870 167.475 ;
        RECT 7.455 163.095 41.125 163.105 ;
        RECT 7.455 162.905 42.425 163.095 ;
        RECT 7.455 162.895 41.125 162.905 ;
        RECT 5.925 161.800 7.200 161.975 ;
        RECT 8.970 157.625 41.125 162.895 ;
        RECT 42.685 161.795 43.870 161.995 ;
        RECT 7.455 157.615 41.125 157.625 ;
        RECT 7.455 157.425 42.425 157.615 ;
        RECT 7.455 157.415 41.125 157.425 ;
        RECT 5.925 156.320 7.200 156.495 ;
        RECT 8.970 152.145 41.125 157.415 ;
        RECT 42.685 156.315 43.870 156.515 ;
        RECT 7.455 152.135 41.125 152.145 ;
        RECT 7.455 151.945 42.425 152.135 ;
        RECT 7.455 151.935 41.125 151.945 ;
        RECT 5.925 150.840 7.200 151.015 ;
        RECT 8.970 146.665 41.125 151.935 ;
        RECT 42.685 150.835 43.870 151.035 ;
        RECT 7.455 146.655 41.125 146.665 ;
        RECT 7.455 146.465 42.425 146.655 ;
        RECT 7.455 146.455 41.125 146.465 ;
        RECT 5.925 145.360 7.200 145.535 ;
        RECT 8.970 141.185 41.125 146.455 ;
        RECT 42.685 145.355 43.870 145.555 ;
        RECT 7.455 141.175 41.125 141.185 ;
        RECT 7.455 140.985 42.425 141.175 ;
        RECT 7.455 140.975 41.125 140.985 ;
        RECT 5.925 139.880 7.200 140.055 ;
        RECT 8.970 135.705 41.125 140.975 ;
        RECT 42.685 139.875 43.870 140.075 ;
        RECT 7.455 135.695 41.125 135.705 ;
        RECT 7.455 135.505 42.425 135.695 ;
        RECT 7.455 135.495 41.125 135.505 ;
        RECT 5.925 134.400 7.200 134.575 ;
        RECT 8.970 130.225 41.125 135.495 ;
        RECT 42.685 134.395 43.870 134.595 ;
        RECT 7.455 130.215 41.125 130.225 ;
        RECT 7.455 130.025 42.425 130.215 ;
        RECT 7.455 130.015 41.125 130.025 ;
        RECT 5.925 128.920 7.200 129.095 ;
        RECT 8.970 124.745 41.125 130.015 ;
        RECT 42.685 128.915 43.870 129.115 ;
        RECT 7.455 124.735 41.125 124.745 ;
        RECT 7.455 124.545 42.425 124.735 ;
        RECT 7.455 124.535 41.125 124.545 ;
        RECT 5.925 123.440 7.200 123.615 ;
        RECT 8.970 119.265 41.125 124.535 ;
        RECT 42.685 123.435 43.870 123.635 ;
        RECT 7.455 119.255 41.125 119.265 ;
        RECT 7.455 119.065 42.425 119.255 ;
        RECT 7.455 119.055 41.125 119.065 ;
        RECT 5.925 117.960 7.200 118.135 ;
        RECT 8.970 113.785 41.125 119.055 ;
        RECT 42.685 117.955 43.870 118.155 ;
        RECT 7.455 113.775 41.125 113.785 ;
        RECT 7.455 113.585 42.425 113.775 ;
        RECT 7.455 113.575 41.125 113.585 ;
        RECT 5.925 112.480 7.200 112.655 ;
        RECT 8.970 108.305 41.125 113.575 ;
        RECT 42.685 112.475 43.870 112.675 ;
        RECT 7.455 108.295 41.125 108.305 ;
        RECT 7.455 108.105 42.425 108.295 ;
        RECT 7.455 108.095 41.125 108.105 ;
        RECT 5.925 107.000 7.200 107.175 ;
        RECT 8.970 102.825 41.125 108.095 ;
        RECT 42.685 106.995 43.870 107.195 ;
        RECT 7.455 102.815 41.125 102.825 ;
        RECT 7.455 102.625 42.425 102.815 ;
        RECT 7.455 102.615 41.125 102.625 ;
        RECT 5.925 101.520 7.200 101.695 ;
        RECT 8.970 97.345 41.125 102.615 ;
        RECT 42.685 101.515 43.870 101.715 ;
        RECT 7.455 97.335 41.125 97.345 ;
        RECT 7.455 97.145 42.425 97.335 ;
        RECT 7.455 97.135 41.125 97.145 ;
        RECT 5.925 96.040 7.200 96.215 ;
        RECT 8.970 91.865 41.125 97.135 ;
        RECT 42.685 96.035 43.870 96.235 ;
        RECT 7.455 91.855 41.125 91.865 ;
        RECT 7.455 91.665 42.425 91.855 ;
        RECT 7.455 91.655 41.125 91.665 ;
        RECT 5.925 90.560 7.200 90.735 ;
        RECT 8.970 86.385 41.125 91.655 ;
        RECT 42.685 90.555 43.870 90.755 ;
        RECT 7.455 86.375 41.125 86.385 ;
        RECT 7.455 86.185 42.425 86.375 ;
        RECT 7.455 86.175 41.125 86.185 ;
        RECT 5.925 85.080 7.200 85.255 ;
        RECT 8.970 80.905 41.125 86.175 ;
        RECT 42.685 85.075 43.870 85.275 ;
        RECT 7.455 80.895 41.125 80.905 ;
        RECT 7.455 80.705 42.425 80.895 ;
        RECT 7.455 80.695 41.125 80.705 ;
        RECT 5.925 79.600 7.200 79.775 ;
        RECT 8.970 75.425 41.125 80.695 ;
        RECT 42.685 79.595 43.870 79.795 ;
        RECT 7.455 75.415 41.125 75.425 ;
        RECT 7.455 75.225 42.425 75.415 ;
        RECT 7.455 75.215 41.125 75.225 ;
        RECT 5.925 74.120 7.200 74.295 ;
        RECT 8.970 69.945 41.125 75.215 ;
        RECT 42.685 74.115 43.870 74.315 ;
        RECT 7.455 69.935 41.125 69.945 ;
        RECT 7.455 69.745 42.425 69.935 ;
        RECT 7.455 69.735 41.125 69.745 ;
        RECT 5.925 68.640 7.200 68.815 ;
        RECT 8.970 64.465 41.125 69.735 ;
        RECT 42.685 68.635 43.870 68.835 ;
        RECT 7.455 64.455 41.125 64.465 ;
        RECT 7.455 64.265 42.425 64.455 ;
        RECT 7.455 64.255 41.125 64.265 ;
        RECT 5.925 63.160 7.200 63.335 ;
        RECT 8.970 58.985 41.125 64.255 ;
        RECT 42.685 63.155 43.870 63.355 ;
        RECT 7.455 58.975 41.125 58.985 ;
        RECT 7.455 58.785 42.425 58.975 ;
        RECT 7.455 58.775 41.125 58.785 ;
        RECT 5.925 57.680 7.200 57.855 ;
        RECT 8.970 53.505 41.125 58.775 ;
        RECT 42.685 57.675 43.870 57.875 ;
        RECT 7.455 53.495 41.125 53.505 ;
        RECT 7.455 53.305 42.425 53.495 ;
        RECT 7.455 53.295 41.125 53.305 ;
        RECT 5.925 52.200 7.200 52.375 ;
        RECT 8.970 48.025 41.125 53.295 ;
        RECT 42.685 52.195 43.870 52.395 ;
        RECT 7.455 48.015 41.125 48.025 ;
        RECT 7.455 47.825 42.425 48.015 ;
        RECT 7.455 47.815 41.125 47.825 ;
        RECT 5.925 46.720 7.200 46.895 ;
        RECT 8.970 42.545 41.125 47.815 ;
        RECT 42.685 46.715 43.870 46.915 ;
        RECT 7.455 42.535 41.125 42.545 ;
        RECT 7.455 42.345 42.425 42.535 ;
        RECT 7.455 42.335 41.125 42.345 ;
        RECT 5.925 41.240 7.200 41.415 ;
        RECT 8.970 37.065 41.125 42.335 ;
        RECT 42.685 41.235 43.870 41.435 ;
        RECT 7.455 37.055 41.125 37.065 ;
        RECT 7.455 36.865 42.425 37.055 ;
        RECT 7.455 36.855 41.125 36.865 ;
        RECT 5.925 35.760 7.200 35.935 ;
        RECT 8.970 31.585 41.125 36.855 ;
        RECT 42.685 35.755 43.870 35.955 ;
        RECT 7.455 31.575 41.125 31.585 ;
        RECT 7.455 31.385 42.425 31.575 ;
        RECT 7.455 31.375 41.125 31.385 ;
        RECT 5.925 30.280 7.200 30.455 ;
        RECT 8.970 26.105 41.125 31.375 ;
        RECT 42.685 30.275 43.870 30.475 ;
        RECT 7.455 26.095 41.125 26.105 ;
        RECT 7.455 25.905 42.425 26.095 ;
        RECT 7.455 25.895 41.125 25.905 ;
        RECT 5.925 24.800 7.200 24.975 ;
        RECT 8.970 20.625 41.125 25.895 ;
        RECT 42.685 24.795 43.870 24.995 ;
        RECT 7.455 20.615 41.125 20.625 ;
        RECT 7.455 20.425 42.425 20.615 ;
        RECT 7.455 20.415 41.125 20.425 ;
        RECT 5.925 19.320 7.200 19.495 ;
        RECT 8.970 15.145 41.125 20.415 ;
        RECT 42.685 19.315 43.870 19.515 ;
        RECT 7.455 15.135 41.125 15.145 ;
        RECT 7.455 14.945 42.425 15.135 ;
        RECT 7.455 14.940 41.125 14.945 ;
        RECT 5.925 13.840 7.200 14.015 ;
        RECT 8.970 9.665 41.125 14.940 ;
        RECT 42.685 13.835 43.870 14.035 ;
        RECT 7.455 9.655 41.125 9.665 ;
        RECT 7.455 9.465 42.425 9.655 ;
        RECT 7.455 8.535 41.125 9.465 ;
        RECT 5.925 8.360 41.125 8.535 ;
        RECT 7.455 8.335 41.125 8.360 ;
        RECT 42.685 8.355 43.870 8.555 ;
        RECT 8.970 4.175 41.125 8.335 ;
        RECT 8.970 3.985 42.425 4.175 ;
        RECT 8.970 1.155 41.125 3.985 ;
        RECT 42.685 2.875 43.870 3.075 ;
        RECT 8.970 1.150 14.185 1.155 ;
        RECT 15.745 1.150 17.305 1.155 ;
        RECT 18.865 1.150 20.415 1.155 ;
        RECT 21.975 1.150 23.525 1.155 ;
        RECT 25.085 1.150 26.635 1.155 ;
        RECT 28.195 1.150 29.745 1.155 ;
        RECT 31.305 1.150 32.855 1.155 ;
        RECT 34.415 1.150 35.965 1.155 ;
        RECT 8.970 0.850 12.925 1.150 ;
        RECT 15.745 0.850 16.035 1.150 ;
        RECT 18.865 0.850 19.145 1.150 ;
        RECT 21.975 0.850 22.255 1.150 ;
        RECT 25.085 0.850 25.365 1.150 ;
        RECT 28.195 0.850 28.475 1.150 ;
        RECT 31.305 0.850 31.585 1.150 ;
        RECT 34.415 0.850 34.695 1.150 ;
        RECT 37.525 0.850 41.125 1.155 ;
      LAYER Metal4 ;
        RECT 25.595 178.500 27.825 178.800 ;
        RECT 22.485 177.130 30.935 178.500 ;
        RECT 19.375 175.760 34.045 177.130 ;
        RECT 15.985 174.620 35.345 175.760 ;
        RECT 25.595 173.020 27.825 174.620 ;
        RECT 22.485 171.650 30.935 173.020 ;
        RECT 19.375 170.280 34.045 171.650 ;
        RECT 15.985 169.140 35.345 170.280 ;
        RECT 25.595 167.540 27.825 169.140 ;
        RECT 22.485 166.170 30.935 167.540 ;
        RECT 19.375 164.800 34.045 166.170 ;
        RECT 15.985 163.660 35.345 164.800 ;
        RECT 25.595 162.060 27.825 163.660 ;
        RECT 22.485 160.690 30.935 162.060 ;
        RECT 19.375 159.320 34.045 160.690 ;
        RECT 15.985 158.180 35.345 159.320 ;
        RECT 25.595 156.580 27.825 158.180 ;
        RECT 22.485 155.210 30.935 156.580 ;
        RECT 19.375 153.840 34.045 155.210 ;
        RECT 15.985 152.700 35.345 153.840 ;
        RECT 25.595 151.100 27.825 152.700 ;
        RECT 22.485 149.730 30.935 151.100 ;
        RECT 19.375 148.360 34.045 149.730 ;
        RECT 15.985 147.220 35.345 148.360 ;
        RECT 25.595 145.620 27.825 147.220 ;
        RECT 22.485 144.250 30.935 145.620 ;
        RECT 19.375 142.880 34.045 144.250 ;
        RECT 15.985 141.740 35.345 142.880 ;
        RECT 25.595 140.140 27.825 141.740 ;
        RECT 22.485 138.770 30.935 140.140 ;
        RECT 19.375 137.400 34.045 138.770 ;
        RECT 15.985 136.260 35.345 137.400 ;
        RECT 25.595 134.660 27.825 136.260 ;
        RECT 22.485 133.290 30.935 134.660 ;
        RECT 19.375 131.920 34.045 133.290 ;
        RECT 15.985 130.780 35.345 131.920 ;
        RECT 25.595 129.180 27.825 130.780 ;
        RECT 22.485 127.810 30.935 129.180 ;
        RECT 19.375 126.440 34.045 127.810 ;
        RECT 15.985 125.300 35.345 126.440 ;
        RECT 25.595 123.700 27.825 125.300 ;
        RECT 22.485 122.330 30.935 123.700 ;
        RECT 19.375 120.960 34.045 122.330 ;
        RECT 15.985 119.820 35.345 120.960 ;
        RECT 25.595 118.220 27.825 119.820 ;
        RECT 22.485 116.850 30.935 118.220 ;
        RECT 19.375 115.480 34.045 116.850 ;
        RECT 15.985 114.340 35.345 115.480 ;
        RECT 25.595 112.740 27.825 114.340 ;
        RECT 22.485 111.370 30.935 112.740 ;
        RECT 19.375 110.000 34.045 111.370 ;
        RECT 15.985 108.860 35.345 110.000 ;
        RECT 25.595 107.260 27.825 108.860 ;
        RECT 22.485 105.890 30.935 107.260 ;
        RECT 19.375 104.520 34.045 105.890 ;
        RECT 15.985 103.380 35.345 104.520 ;
        RECT 25.595 101.780 27.825 103.380 ;
        RECT 22.485 100.410 30.935 101.780 ;
        RECT 19.375 99.040 34.045 100.410 ;
        RECT 15.985 97.900 35.345 99.040 ;
        RECT 25.595 96.300 27.825 97.900 ;
        RECT 22.485 94.930 30.935 96.300 ;
        RECT 19.375 93.560 34.045 94.930 ;
        RECT 15.985 92.420 35.345 93.560 ;
        RECT 25.595 90.820 27.825 92.420 ;
        RECT 22.485 89.450 30.935 90.820 ;
        RECT 19.375 88.080 34.045 89.450 ;
        RECT 15.985 86.940 35.345 88.080 ;
        RECT 25.595 85.340 27.825 86.940 ;
        RECT 22.485 83.970 30.935 85.340 ;
        RECT 19.375 82.600 34.045 83.970 ;
        RECT 15.985 81.460 35.345 82.600 ;
        RECT 25.595 79.860 27.825 81.460 ;
        RECT 22.485 78.490 30.935 79.860 ;
        RECT 19.375 77.120 34.045 78.490 ;
        RECT 15.985 75.980 35.345 77.120 ;
        RECT 25.595 74.380 27.825 75.980 ;
        RECT 22.485 73.010 30.935 74.380 ;
        RECT 19.375 71.640 34.045 73.010 ;
        RECT 15.985 70.500 35.345 71.640 ;
        RECT 25.595 68.900 27.825 70.500 ;
        RECT 22.485 67.530 30.935 68.900 ;
        RECT 19.375 66.160 34.045 67.530 ;
        RECT 15.985 65.020 35.345 66.160 ;
        RECT 25.595 63.420 27.825 65.020 ;
        RECT 22.485 62.050 30.935 63.420 ;
        RECT 19.375 60.680 34.045 62.050 ;
        RECT 15.985 59.540 35.345 60.680 ;
        RECT 25.595 57.940 27.825 59.540 ;
        RECT 22.485 56.570 30.935 57.940 ;
        RECT 19.375 55.200 34.045 56.570 ;
        RECT 15.985 54.060 35.345 55.200 ;
        RECT 25.595 52.460 27.825 54.060 ;
        RECT 22.485 51.090 30.935 52.460 ;
        RECT 19.375 49.720 34.045 51.090 ;
        RECT 15.985 48.580 35.345 49.720 ;
        RECT 25.595 46.980 27.825 48.580 ;
        RECT 22.485 45.610 30.935 46.980 ;
        RECT 19.375 44.240 34.045 45.610 ;
        RECT 15.985 43.100 35.345 44.240 ;
        RECT 25.595 41.500 27.825 43.100 ;
        RECT 22.485 40.130 30.935 41.500 ;
        RECT 19.375 38.760 34.045 40.130 ;
        RECT 15.985 37.620 35.345 38.760 ;
        RECT 25.595 36.020 27.825 37.620 ;
        RECT 22.485 34.650 30.935 36.020 ;
        RECT 19.375 33.280 34.045 34.650 ;
        RECT 15.985 32.140 35.345 33.280 ;
        RECT 25.595 30.540 27.825 32.140 ;
        RECT 22.485 29.170 30.935 30.540 ;
        RECT 19.375 27.800 34.045 29.170 ;
        RECT 15.985 26.660 35.345 27.800 ;
        RECT 25.595 25.060 27.825 26.660 ;
        RECT 22.485 23.690 30.935 25.060 ;
        RECT 19.375 22.320 34.045 23.690 ;
        RECT 15.985 21.180 35.345 22.320 ;
        RECT 25.595 19.580 27.825 21.180 ;
        RECT 22.485 18.210 30.935 19.580 ;
        RECT 19.375 16.840 34.045 18.210 ;
        RECT 15.985 15.700 35.345 16.840 ;
        RECT 25.595 14.100 27.825 15.700 ;
        RECT 22.485 12.730 30.935 14.100 ;
        RECT 19.375 11.360 34.045 12.730 ;
        RECT 15.985 10.220 35.345 11.360 ;
        RECT 25.595 8.620 27.825 10.220 ;
        RECT 22.485 7.250 30.935 8.620 ;
        RECT 19.375 5.880 34.045 7.250 ;
        RECT 15.985 4.810 35.345 5.880 ;
  END
END sram_32x8_9T
END LIBRARY

